VERSION 5.8 ;
BUSBITCHARS "[]" ;
DIVIDERCHAR "/" ;
UNITS
    DATABASE MICRONS 1000 ;
END UNITS

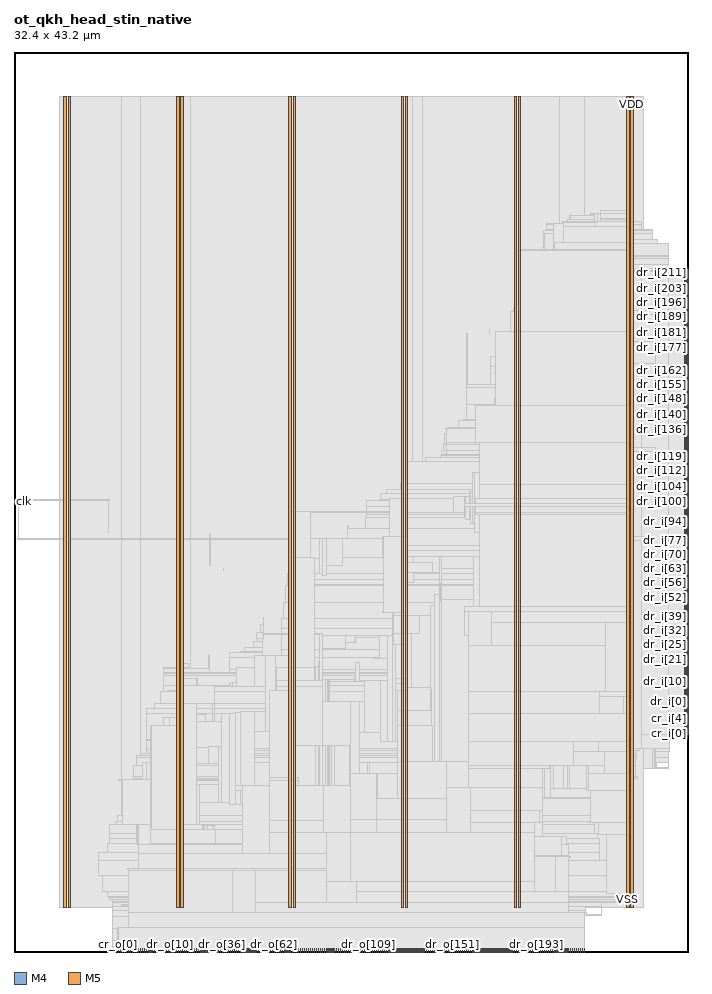
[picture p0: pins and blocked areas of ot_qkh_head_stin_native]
MACRO ot_qkh_head_stin_native
  FOREIGN ot_qkh_head_stin_native 0 0 ;
  CLASS BLOCK ;
  SIZE 32.4 BY 43.2 ;
  PIN clk
    DIRECTION INPUT ;
    USE SIGNAL ;
    PORT
      LAYER M4 ;
        RECT  0 21.6 0.192 21.624 ;
    END
  END clk
  PIN cr_i[0]
    DIRECTION INPUT ;
    USE SIGNAL ;
    PORT
      LAYER M4 ;
        RECT  32.208 10.464 32.4 10.488 ;
    END
  END cr_i[0]
  PIN cr_i[10]
    DIRECTION INPUT ;
    USE SIGNAL ;
    PORT
      LAYER M4 ;
        RECT  32.208 11.424 32.4 11.448 ;
    END
  END cr_i[10]
  PIN cr_i[11]
    DIRECTION INPUT ;
    USE SIGNAL ;
    PORT
      LAYER M4 ;
        RECT  32.208 11.52 32.4 11.544 ;
    END
  END cr_i[11]
  PIN cr_i[12]
    DIRECTION INPUT ;
    USE SIGNAL ;
    PORT
      LAYER M4 ;
        RECT  32.208 11.616 32.4 11.64 ;
    END
  END cr_i[12]
  PIN cr_i[13]
    DIRECTION INPUT ;
    USE SIGNAL ;
    PORT
      LAYER M4 ;
        RECT  32.208 11.712 32.4 11.736 ;
    END
  END cr_i[13]
  PIN cr_i[14]
    DIRECTION INPUT ;
    USE SIGNAL ;
    PORT
      LAYER M4 ;
        RECT  32.208 11.808 32.4 11.832 ;
    END
  END cr_i[14]
  PIN cr_i[15]
    DIRECTION INPUT ;
    USE SIGNAL ;
    PORT
      LAYER M4 ;
        RECT  32.208 11.904 32.4 11.928 ;
    END
  END cr_i[15]
  PIN cr_i[1]
    DIRECTION INPUT ;
    USE SIGNAL ;
    PORT
      LAYER M4 ;
        RECT  32.208 10.56 32.4 10.584 ;
    END
  END cr_i[1]
  PIN cr_i[2]
    DIRECTION INPUT ;
    USE SIGNAL ;
    PORT
      LAYER M4 ;
        RECT  32.208 10.656 32.4 10.68 ;
    END
  END cr_i[2]
  PIN cr_i[3]
    DIRECTION INPUT ;
    USE SIGNAL ;
    PORT
      LAYER M4 ;
        RECT  32.208 10.752 32.4 10.776 ;
    END
  END cr_i[3]
  PIN cr_i[4]
    DIRECTION INPUT ;
    USE SIGNAL ;
    PORT
      LAYER M4 ;
        RECT  32.208 10.848 32.4 10.872 ;
    END
  END cr_i[4]
  PIN cr_i[5]
    DIRECTION INPUT ;
    USE SIGNAL ;
    PORT
      LAYER M4 ;
        RECT  32.208 10.944 32.4 10.968 ;
    END
  END cr_i[5]
  PIN cr_i[6]
    DIRECTION INPUT ;
    USE SIGNAL ;
    PORT
      LAYER M4 ;
        RECT  32.208 11.04 32.4 11.064 ;
    END
  END cr_i[6]
  PIN cr_i[7]
    DIRECTION INPUT ;
    USE SIGNAL ;
    PORT
      LAYER M4 ;
        RECT  32.208 11.136 32.4 11.16 ;
    END
  END cr_i[7]
  PIN cr_i[8]
    DIRECTION INPUT ;
    USE SIGNAL ;
    PORT
      LAYER M4 ;
        RECT  32.208 11.232 32.4 11.256 ;
    END
  END cr_i[8]
  PIN cr_i[9]
    DIRECTION INPUT ;
    USE SIGNAL ;
    PORT
      LAYER M4 ;
        RECT  32.208 11.328 32.4 11.352 ;
    END
  END cr_i[9]
  PIN cr_o[0]
    DIRECTION OUTPUT ;
    USE SIGNAL ;
    PORT
      LAYER M5 ;
        RECT  4.992 0 5.016 0.192 ;
    END
  END cr_o[0]
  PIN cr_o[10]
    DIRECTION OUTPUT ;
    USE SIGNAL ;
    PORT
      LAYER M5 ;
        RECT  5.952 0 5.976 0.192 ;
    END
  END cr_o[10]
  PIN cr_o[11]
    DIRECTION OUTPUT ;
    USE SIGNAL ;
    PORT
      LAYER M5 ;
        RECT  6.048 0 6.072 0.192 ;
    END
  END cr_o[11]
  PIN cr_o[12]
    DIRECTION OUTPUT ;
    USE SIGNAL ;
    PORT
      LAYER M5 ;
        RECT  6.144 0 6.168 0.192 ;
    END
  END cr_o[12]
  PIN cr_o[13]
    DIRECTION OUTPUT ;
    USE SIGNAL ;
    PORT
      LAYER M5 ;
        RECT  6.24 0 6.264 0.192 ;
    END
  END cr_o[13]
  PIN cr_o[14]
    DIRECTION OUTPUT ;
    USE SIGNAL ;
    PORT
      LAYER M5 ;
        RECT  6.336 0 6.36 0.192 ;
    END
  END cr_o[14]
  PIN cr_o[15]
    DIRECTION OUTPUT ;
    USE SIGNAL ;
    PORT
      LAYER M5 ;
        RECT  6.432 0 6.456 0.192 ;
    END
  END cr_o[15]
  PIN cr_o[1]
    DIRECTION OUTPUT ;
    USE SIGNAL ;
    PORT
      LAYER M5 ;
        RECT  5.088 0 5.112 0.192 ;
    END
  END cr_o[1]
  PIN cr_o[2]
    DIRECTION OUTPUT ;
    USE SIGNAL ;
    PORT
      LAYER M5 ;
        RECT  5.184 0 5.208 0.192 ;
    END
  END cr_o[2]
  PIN cr_o[3]
    DIRECTION OUTPUT ;
    USE SIGNAL ;
    PORT
      LAYER M5 ;
        RECT  5.28 0 5.304 0.192 ;
    END
  END cr_o[3]
  PIN cr_o[4]
    DIRECTION OUTPUT ;
    USE SIGNAL ;
    PORT
      LAYER M5 ;
        RECT  5.376 0 5.4 0.192 ;
    END
  END cr_o[4]
  PIN cr_o[5]
    DIRECTION OUTPUT ;
    USE SIGNAL ;
    PORT
      LAYER M5 ;
        RECT  5.472 0 5.496 0.192 ;
    END
  END cr_o[5]
  PIN cr_o[6]
    DIRECTION OUTPUT ;
    USE SIGNAL ;
    PORT
      LAYER M5 ;
        RECT  5.568 0 5.592 0.192 ;
    END
  END cr_o[6]
  PIN cr_o[7]
    DIRECTION OUTPUT ;
    USE SIGNAL ;
    PORT
      LAYER M5 ;
        RECT  5.664 0 5.688 0.192 ;
    END
  END cr_o[7]
  PIN cr_o[8]
    DIRECTION OUTPUT ;
    USE SIGNAL ;
    PORT
      LAYER M5 ;
        RECT  5.76 0 5.784 0.192 ;
    END
  END cr_o[8]
  PIN cr_o[9]
    DIRECTION OUTPUT ;
    USE SIGNAL ;
    PORT
      LAYER M5 ;
        RECT  5.856 0 5.88 0.192 ;
    END
  END cr_o[9]
  PIN dr_i[0]
    DIRECTION INPUT ;
    USE SIGNAL ;
    PORT
      LAYER M4 ;
        RECT  32.208 12 32.4 12.024 ;
    END
  END dr_i[0]
  PIN dr_i[100]
    DIRECTION INPUT ;
    USE SIGNAL ;
    PORT
      LAYER M4 ;
        RECT  32.208 21.6 32.4 21.624 ;
    END
  END dr_i[100]
  PIN dr_i[101]
    DIRECTION INPUT ;
    USE SIGNAL ;
    PORT
      LAYER M4 ;
        RECT  32.208 21.696 32.4 21.72 ;
    END
  END dr_i[101]
  PIN dr_i[102]
    DIRECTION INPUT ;
    USE SIGNAL ;
    PORT
      LAYER M4 ;
        RECT  32.208 21.792 32.4 21.816 ;
    END
  END dr_i[102]
  PIN dr_i[103]
    DIRECTION INPUT ;
    USE SIGNAL ;
    PORT
      LAYER M4 ;
        RECT  32.208 21.888 32.4 21.912 ;
    END
  END dr_i[103]
  PIN dr_i[104]
    DIRECTION INPUT ;
    USE SIGNAL ;
    PORT
      LAYER M4 ;
        RECT  32.208 21.984 32.4 22.008 ;
    END
  END dr_i[104]
  PIN dr_i[105]
    DIRECTION INPUT ;
    USE SIGNAL ;
    PORT
      LAYER M4 ;
        RECT  32.208 22.08 32.4 22.104 ;
    END
  END dr_i[105]
  PIN dr_i[106]
    DIRECTION INPUT ;
    USE SIGNAL ;
    PORT
      LAYER M4 ;
        RECT  32.208 22.176 32.4 22.2 ;
    END
  END dr_i[106]
  PIN dr_i[107]
    DIRECTION INPUT ;
    USE SIGNAL ;
    PORT
      LAYER M4 ;
        RECT  32.208 22.272 32.4 22.296 ;
    END
  END dr_i[107]
  PIN dr_i[108]
    DIRECTION INPUT ;
    USE SIGNAL ;
    PORT
      LAYER M4 ;
        RECT  32.208 22.368 32.4 22.392 ;
    END
  END dr_i[108]
  PIN dr_i[109]
    DIRECTION INPUT ;
    USE SIGNAL ;
    PORT
      LAYER M4 ;
        RECT  32.208 22.464 32.4 22.488 ;
    END
  END dr_i[109]
  PIN dr_i[10]
    DIRECTION INPUT ;
    USE SIGNAL ;
    PORT
      LAYER M4 ;
        RECT  32.208 12.96 32.4 12.984 ;
    END
  END dr_i[10]
  PIN dr_i[110]
    DIRECTION INPUT ;
    USE SIGNAL ;
    PORT
      LAYER M4 ;
        RECT  32.208 22.56 32.4 22.584 ;
    END
  END dr_i[110]
  PIN dr_i[111]
    DIRECTION INPUT ;
    USE SIGNAL ;
    PORT
      LAYER M4 ;
        RECT  32.208 22.656 32.4 22.68 ;
    END
  END dr_i[111]
  PIN dr_i[112]
    DIRECTION INPUT ;
    USE SIGNAL ;
    PORT
      LAYER M4 ;
        RECT  32.208 22.752 32.4 22.776 ;
    END
  END dr_i[112]
  PIN dr_i[113]
    DIRECTION INPUT ;
    USE SIGNAL ;
    PORT
      LAYER M4 ;
        RECT  32.208 22.848 32.4 22.872 ;
    END
  END dr_i[113]
  PIN dr_i[114]
    DIRECTION INPUT ;
    USE SIGNAL ;
    PORT
      LAYER M4 ;
        RECT  32.208 22.944 32.4 22.968 ;
    END
  END dr_i[114]
  PIN dr_i[115]
    DIRECTION INPUT ;
    USE SIGNAL ;
    PORT
      LAYER M4 ;
        RECT  32.208 23.04 32.4 23.064 ;
    END
  END dr_i[115]
  PIN dr_i[116]
    DIRECTION INPUT ;
    USE SIGNAL ;
    PORT
      LAYER M4 ;
        RECT  32.208 23.136 32.4 23.16 ;
    END
  END dr_i[116]
  PIN dr_i[117]
    DIRECTION INPUT ;
    USE SIGNAL ;
    PORT
      LAYER M4 ;
        RECT  32.208 23.232 32.4 23.256 ;
    END
  END dr_i[117]
  PIN dr_i[118]
    DIRECTION INPUT ;
    USE SIGNAL ;
    PORT
      LAYER M4 ;
        RECT  32.208 23.328 32.4 23.352 ;
    END
  END dr_i[118]
  PIN dr_i[119]
    DIRECTION INPUT ;
    USE SIGNAL ;
    PORT
      LAYER M4 ;
        RECT  32.208 23.424 32.4 23.448 ;
    END
  END dr_i[119]
  PIN dr_i[11]
    DIRECTION INPUT ;
    USE SIGNAL ;
    PORT
      LAYER M4 ;
        RECT  32.208 13.056 32.4 13.08 ;
    END
  END dr_i[11]
  PIN dr_i[120]
    DIRECTION INPUT ;
    USE SIGNAL ;
    PORT
      LAYER M4 ;
        RECT  32.208 23.52 32.4 23.544 ;
    END
  END dr_i[120]
  PIN dr_i[121]
    DIRECTION INPUT ;
    USE SIGNAL ;
    PORT
      LAYER M4 ;
        RECT  32.208 23.616 32.4 23.64 ;
    END
  END dr_i[121]
  PIN dr_i[122]
    DIRECTION INPUT ;
    USE SIGNAL ;
    PORT
      LAYER M4 ;
        RECT  32.208 23.712 32.4 23.736 ;
    END
  END dr_i[122]
  PIN dr_i[123]
    DIRECTION INPUT ;
    USE SIGNAL ;
    PORT
      LAYER M4 ;
        RECT  32.208 23.808 32.4 23.832 ;
    END
  END dr_i[123]
  PIN dr_i[124]
    DIRECTION INPUT ;
    USE SIGNAL ;
    PORT
      LAYER M4 ;
        RECT  32.208 23.904 32.4 23.928 ;
    END
  END dr_i[124]
  PIN dr_i[125]
    DIRECTION INPUT ;
    USE SIGNAL ;
    PORT
      LAYER M4 ;
        RECT  32.208 24 32.4 24.024 ;
    END
  END dr_i[125]
  PIN dr_i[126]
    DIRECTION INPUT ;
    USE SIGNAL ;
    PORT
      LAYER M4 ;
        RECT  32.208 24.096 32.4 24.12 ;
    END
  END dr_i[126]
  PIN dr_i[127]
    DIRECTION INPUT ;
    USE SIGNAL ;
    PORT
      LAYER M4 ;
        RECT  32.208 24.192 32.4 24.216 ;
    END
  END dr_i[127]
  PIN dr_i[128]
    DIRECTION INPUT ;
    USE SIGNAL ;
    PORT
      LAYER M4 ;
        RECT  32.208 24.288 32.4 24.312 ;
    END
  END dr_i[128]
  PIN dr_i[129]
    DIRECTION INPUT ;
    USE SIGNAL ;
    PORT
      LAYER M4 ;
        RECT  32.208 24.384 32.4 24.408 ;
    END
  END dr_i[129]
  PIN dr_i[12]
    DIRECTION INPUT ;
    USE SIGNAL ;
    PORT
      LAYER M4 ;
        RECT  32.208 13.152 32.4 13.176 ;
    END
  END dr_i[12]
  PIN dr_i[130]
    DIRECTION INPUT ;
    USE SIGNAL ;
    PORT
      LAYER M4 ;
        RECT  32.208 24.48 32.4 24.504 ;
    END
  END dr_i[130]
  PIN dr_i[131]
    DIRECTION INPUT ;
    USE SIGNAL ;
    PORT
      LAYER M4 ;
        RECT  32.208 24.576 32.4 24.6 ;
    END
  END dr_i[131]
  PIN dr_i[132]
    DIRECTION INPUT ;
    USE SIGNAL ;
    PORT
      LAYER M4 ;
        RECT  32.208 24.672 32.4 24.696 ;
    END
  END dr_i[132]
  PIN dr_i[133]
    DIRECTION INPUT ;
    USE SIGNAL ;
    PORT
      LAYER M4 ;
        RECT  32.208 24.768 32.4 24.792 ;
    END
  END dr_i[133]
  PIN dr_i[134]
    DIRECTION INPUT ;
    USE SIGNAL ;
    PORT
      LAYER M4 ;
        RECT  32.208 24.864 32.4 24.888 ;
    END
  END dr_i[134]
  PIN dr_i[135]
    DIRECTION INPUT ;
    USE SIGNAL ;
    PORT
      LAYER M4 ;
        RECT  32.208 24.96 32.4 24.984 ;
    END
  END dr_i[135]
  PIN dr_i[136]
    DIRECTION INPUT ;
    USE SIGNAL ;
    PORT
      LAYER M4 ;
        RECT  32.208 25.056 32.4 25.08 ;
    END
  END dr_i[136]
  PIN dr_i[137]
    DIRECTION INPUT ;
    USE SIGNAL ;
    PORT
      LAYER M4 ;
        RECT  32.208 25.152 32.4 25.176 ;
    END
  END dr_i[137]
  PIN dr_i[138]
    DIRECTION INPUT ;
    USE SIGNAL ;
    PORT
      LAYER M4 ;
        RECT  32.208 25.248 32.4 25.272 ;
    END
  END dr_i[138]
  PIN dr_i[139]
    DIRECTION INPUT ;
    USE SIGNAL ;
    PORT
      LAYER M4 ;
        RECT  32.208 25.344 32.4 25.368 ;
    END
  END dr_i[139]
  PIN dr_i[13]
    DIRECTION INPUT ;
    USE SIGNAL ;
    PORT
      LAYER M4 ;
        RECT  32.208 13.248 32.4 13.272 ;
    END
  END dr_i[13]
  PIN dr_i[140]
    DIRECTION INPUT ;
    USE SIGNAL ;
    PORT
      LAYER M4 ;
        RECT  32.208 25.44 32.4 25.464 ;
    END
  END dr_i[140]
  PIN dr_i[141]
    DIRECTION INPUT ;
    USE SIGNAL ;
    PORT
      LAYER M4 ;
        RECT  32.208 25.536 32.4 25.56 ;
    END
  END dr_i[141]
  PIN dr_i[142]
    DIRECTION INPUT ;
    USE SIGNAL ;
    PORT
      LAYER M4 ;
        RECT  32.208 25.632 32.4 25.656 ;
    END
  END dr_i[142]
  PIN dr_i[143]
    DIRECTION INPUT ;
    USE SIGNAL ;
    PORT
      LAYER M4 ;
        RECT  32.208 25.728 32.4 25.752 ;
    END
  END dr_i[143]
  PIN dr_i[144]
    DIRECTION INPUT ;
    USE SIGNAL ;
    PORT
      LAYER M4 ;
        RECT  32.208 25.824 32.4 25.848 ;
    END
  END dr_i[144]
  PIN dr_i[145]
    DIRECTION INPUT ;
    USE SIGNAL ;
    PORT
      LAYER M4 ;
        RECT  32.208 25.92 32.4 25.944 ;
    END
  END dr_i[145]
  PIN dr_i[146]
    DIRECTION INPUT ;
    USE SIGNAL ;
    PORT
      LAYER M4 ;
        RECT  32.208 26.016 32.4 26.04 ;
    END
  END dr_i[146]
  PIN dr_i[147]
    DIRECTION INPUT ;
    USE SIGNAL ;
    PORT
      LAYER M4 ;
        RECT  32.208 26.112 32.4 26.136 ;
    END
  END dr_i[147]
  PIN dr_i[148]
    DIRECTION INPUT ;
    USE SIGNAL ;
    PORT
      LAYER M4 ;
        RECT  32.208 26.208 32.4 26.232 ;
    END
  END dr_i[148]
  PIN dr_i[149]
    DIRECTION INPUT ;
    USE SIGNAL ;
    PORT
      LAYER M4 ;
        RECT  32.208 26.304 32.4 26.328 ;
    END
  END dr_i[149]
  PIN dr_i[14]
    DIRECTION INPUT ;
    USE SIGNAL ;
    PORT
      LAYER M4 ;
        RECT  32.208 13.344 32.4 13.368 ;
    END
  END dr_i[14]
  PIN dr_i[150]
    DIRECTION INPUT ;
    USE SIGNAL ;
    PORT
      LAYER M4 ;
        RECT  32.208 26.4 32.4 26.424 ;
    END
  END dr_i[150]
  PIN dr_i[151]
    DIRECTION INPUT ;
    USE SIGNAL ;
    PORT
      LAYER M4 ;
        RECT  32.208 26.496 32.4 26.52 ;
    END
  END dr_i[151]
  PIN dr_i[152]
    DIRECTION INPUT ;
    USE SIGNAL ;
    PORT
      LAYER M4 ;
        RECT  32.208 26.592 32.4 26.616 ;
    END
  END dr_i[152]
  PIN dr_i[153]
    DIRECTION INPUT ;
    USE SIGNAL ;
    PORT
      LAYER M4 ;
        RECT  32.208 26.688 32.4 26.712 ;
    END
  END dr_i[153]
  PIN dr_i[154]
    DIRECTION INPUT ;
    USE SIGNAL ;
    PORT
      LAYER M4 ;
        RECT  32.208 26.784 32.4 26.808 ;
    END
  END dr_i[154]
  PIN dr_i[155]
    DIRECTION INPUT ;
    USE SIGNAL ;
    PORT
      LAYER M4 ;
        RECT  32.208 26.88 32.4 26.904 ;
    END
  END dr_i[155]
  PIN dr_i[156]
    DIRECTION INPUT ;
    USE SIGNAL ;
    PORT
      LAYER M4 ;
        RECT  32.208 26.976 32.4 27 ;
    END
  END dr_i[156]
  PIN dr_i[157]
    DIRECTION INPUT ;
    USE SIGNAL ;
    PORT
      LAYER M4 ;
        RECT  32.208 27.072 32.4 27.096 ;
    END
  END dr_i[157]
  PIN dr_i[158]
    DIRECTION INPUT ;
    USE SIGNAL ;
    PORT
      LAYER M4 ;
        RECT  32.208 27.168 32.4 27.192 ;
    END
  END dr_i[158]
  PIN dr_i[159]
    DIRECTION INPUT ;
    USE SIGNAL ;
    PORT
      LAYER M4 ;
        RECT  32.208 27.264 32.4 27.288 ;
    END
  END dr_i[159]
  PIN dr_i[15]
    DIRECTION INPUT ;
    USE SIGNAL ;
    PORT
      LAYER M4 ;
        RECT  32.208 13.44 32.4 13.464 ;
    END
  END dr_i[15]
  PIN dr_i[160]
    DIRECTION INPUT ;
    USE SIGNAL ;
    PORT
      LAYER M4 ;
        RECT  32.208 27.36 32.4 27.384 ;
    END
  END dr_i[160]
  PIN dr_i[161]
    DIRECTION INPUT ;
    USE SIGNAL ;
    PORT
      LAYER M4 ;
        RECT  32.208 27.456 32.4 27.48 ;
    END
  END dr_i[161]
  PIN dr_i[162]
    DIRECTION INPUT ;
    USE SIGNAL ;
    PORT
      LAYER M4 ;
        RECT  32.208 27.552 32.4 27.576 ;
    END
  END dr_i[162]
  PIN dr_i[163]
    DIRECTION INPUT ;
    USE SIGNAL ;
    PORT
      LAYER M4 ;
        RECT  32.208 27.648 32.4 27.672 ;
    END
  END dr_i[163]
  PIN dr_i[164]
    DIRECTION INPUT ;
    USE SIGNAL ;
    PORT
      LAYER M4 ;
        RECT  32.208 27.744 32.4 27.768 ;
    END
  END dr_i[164]
  PIN dr_i[165]
    DIRECTION INPUT ;
    USE SIGNAL ;
    PORT
      LAYER M4 ;
        RECT  32.208 27.84 32.4 27.864 ;
    END
  END dr_i[165]
  PIN dr_i[166]
    DIRECTION INPUT ;
    USE SIGNAL ;
    PORT
      LAYER M4 ;
        RECT  32.208 27.936 32.4 27.96 ;
    END
  END dr_i[166]
  PIN dr_i[167]
    DIRECTION INPUT ;
    USE SIGNAL ;
    PORT
      LAYER M4 ;
        RECT  32.208 28.032 32.4 28.056 ;
    END
  END dr_i[167]
  PIN dr_i[168]
    DIRECTION INPUT ;
    USE SIGNAL ;
    PORT
      LAYER M4 ;
        RECT  32.208 28.128 32.4 28.152 ;
    END
  END dr_i[168]
  PIN dr_i[169]
    DIRECTION INPUT ;
    USE SIGNAL ;
    PORT
      LAYER M4 ;
        RECT  32.208 28.224 32.4 28.248 ;
    END
  END dr_i[169]
  PIN dr_i[16]
    DIRECTION INPUT ;
    USE SIGNAL ;
    PORT
      LAYER M4 ;
        RECT  32.208 13.536 32.4 13.56 ;
    END
  END dr_i[16]
  PIN dr_i[170]
    DIRECTION INPUT ;
    USE SIGNAL ;
    PORT
      LAYER M4 ;
        RECT  32.208 28.32 32.4 28.344 ;
    END
  END dr_i[170]
  PIN dr_i[171]
    DIRECTION INPUT ;
    USE SIGNAL ;
    PORT
      LAYER M4 ;
        RECT  32.208 28.416 32.4 28.44 ;
    END
  END dr_i[171]
  PIN dr_i[172]
    DIRECTION INPUT ;
    USE SIGNAL ;
    PORT
      LAYER M4 ;
        RECT  32.208 28.512 32.4 28.536 ;
    END
  END dr_i[172]
  PIN dr_i[173]
    DIRECTION INPUT ;
    USE SIGNAL ;
    PORT
      LAYER M4 ;
        RECT  32.208 28.608 32.4 28.632 ;
    END
  END dr_i[173]
  PIN dr_i[174]
    DIRECTION INPUT ;
    USE SIGNAL ;
    PORT
      LAYER M4 ;
        RECT  32.208 28.704 32.4 28.728 ;
    END
  END dr_i[174]
  PIN dr_i[175]
    DIRECTION INPUT ;
    USE SIGNAL ;
    PORT
      LAYER M4 ;
        RECT  32.208 28.8 32.4 28.824 ;
    END
  END dr_i[175]
  PIN dr_i[176]
    DIRECTION INPUT ;
    USE SIGNAL ;
    PORT
      LAYER M4 ;
        RECT  32.208 28.896 32.4 28.92 ;
    END
  END dr_i[176]
  PIN dr_i[177]
    DIRECTION INPUT ;
    USE SIGNAL ;
    PORT
      LAYER M4 ;
        RECT  32.208 28.992 32.4 29.016 ;
    END
  END dr_i[177]
  PIN dr_i[178]
    DIRECTION INPUT ;
    USE SIGNAL ;
    PORT
      LAYER M4 ;
        RECT  32.208 29.088 32.4 29.112 ;
    END
  END dr_i[178]
  PIN dr_i[179]
    DIRECTION INPUT ;
    USE SIGNAL ;
    PORT
      LAYER M4 ;
        RECT  32.208 29.184 32.4 29.208 ;
    END
  END dr_i[179]
  PIN dr_i[17]
    DIRECTION INPUT ;
    USE SIGNAL ;
    PORT
      LAYER M4 ;
        RECT  32.208 13.632 32.4 13.656 ;
    END
  END dr_i[17]
  PIN dr_i[180]
    DIRECTION INPUT ;
    USE SIGNAL ;
    PORT
      LAYER M4 ;
        RECT  32.208 29.28 32.4 29.304 ;
    END
  END dr_i[180]
  PIN dr_i[181]
    DIRECTION INPUT ;
    USE SIGNAL ;
    PORT
      LAYER M4 ;
        RECT  32.208 29.376 32.4 29.4 ;
    END
  END dr_i[181]
  PIN dr_i[182]
    DIRECTION INPUT ;
    USE SIGNAL ;
    PORT
      LAYER M4 ;
        RECT  32.208 29.472 32.4 29.496 ;
    END
  END dr_i[182]
  PIN dr_i[183]
    DIRECTION INPUT ;
    USE SIGNAL ;
    PORT
      LAYER M4 ;
        RECT  32.208 29.568 32.4 29.592 ;
    END
  END dr_i[183]
  PIN dr_i[184]
    DIRECTION INPUT ;
    USE SIGNAL ;
    PORT
      LAYER M4 ;
        RECT  32.208 29.664 32.4 29.688 ;
    END
  END dr_i[184]
  PIN dr_i[185]
    DIRECTION INPUT ;
    USE SIGNAL ;
    PORT
      LAYER M4 ;
        RECT  32.208 29.76 32.4 29.784 ;
    END
  END dr_i[185]
  PIN dr_i[186]
    DIRECTION INPUT ;
    USE SIGNAL ;
    PORT
      LAYER M4 ;
        RECT  32.208 29.856 32.4 29.88 ;
    END
  END dr_i[186]
  PIN dr_i[187]
    DIRECTION INPUT ;
    USE SIGNAL ;
    PORT
      LAYER M4 ;
        RECT  32.208 29.952 32.4 29.976 ;
    END
  END dr_i[187]
  PIN dr_i[188]
    DIRECTION INPUT ;
    USE SIGNAL ;
    PORT
      LAYER M4 ;
        RECT  32.208 30.048 32.4 30.072 ;
    END
  END dr_i[188]
  PIN dr_i[189]
    DIRECTION INPUT ;
    USE SIGNAL ;
    PORT
      LAYER M4 ;
        RECT  32.208 30.144 32.4 30.168 ;
    END
  END dr_i[189]
  PIN dr_i[18]
    DIRECTION INPUT ;
    USE SIGNAL ;
    PORT
      LAYER M4 ;
        RECT  32.208 13.728 32.4 13.752 ;
    END
  END dr_i[18]
  PIN dr_i[190]
    DIRECTION INPUT ;
    USE SIGNAL ;
    PORT
      LAYER M4 ;
        RECT  32.208 30.24 32.4 30.264 ;
    END
  END dr_i[190]
  PIN dr_i[191]
    DIRECTION INPUT ;
    USE SIGNAL ;
    PORT
      LAYER M4 ;
        RECT  32.208 30.336 32.4 30.36 ;
    END
  END dr_i[191]
  PIN dr_i[192]
    DIRECTION INPUT ;
    USE SIGNAL ;
    PORT
      LAYER M4 ;
        RECT  32.208 30.432 32.4 30.456 ;
    END
  END dr_i[192]
  PIN dr_i[193]
    DIRECTION INPUT ;
    USE SIGNAL ;
    PORT
      LAYER M4 ;
        RECT  32.208 30.528 32.4 30.552 ;
    END
  END dr_i[193]
  PIN dr_i[194]
    DIRECTION INPUT ;
    USE SIGNAL ;
    PORT
      LAYER M4 ;
        RECT  32.208 30.624 32.4 30.648 ;
    END
  END dr_i[194]
  PIN dr_i[195]
    DIRECTION INPUT ;
    USE SIGNAL ;
    PORT
      LAYER M4 ;
        RECT  32.208 30.72 32.4 30.744 ;
    END
  END dr_i[195]
  PIN dr_i[196]
    DIRECTION INPUT ;
    USE SIGNAL ;
    PORT
      LAYER M4 ;
        RECT  32.208 30.816 32.4 30.84 ;
    END
  END dr_i[196]
  PIN dr_i[197]
    DIRECTION INPUT ;
    USE SIGNAL ;
    PORT
      LAYER M4 ;
        RECT  32.208 30.912 32.4 30.936 ;
    END
  END dr_i[197]
  PIN dr_i[198]
    DIRECTION INPUT ;
    USE SIGNAL ;
    PORT
      LAYER M4 ;
        RECT  32.208 31.008 32.4 31.032 ;
    END
  END dr_i[198]
  PIN dr_i[199]
    DIRECTION INPUT ;
    USE SIGNAL ;
    PORT
      LAYER M4 ;
        RECT  32.208 31.104 32.4 31.128 ;
    END
  END dr_i[199]
  PIN dr_i[19]
    DIRECTION INPUT ;
    USE SIGNAL ;
    PORT
      LAYER M4 ;
        RECT  32.208 13.824 32.4 13.848 ;
    END
  END dr_i[19]
  PIN dr_i[1]
    DIRECTION INPUT ;
    USE SIGNAL ;
    PORT
      LAYER M4 ;
        RECT  32.208 12.096 32.4 12.12 ;
    END
  END dr_i[1]
  PIN dr_i[200]
    DIRECTION INPUT ;
    USE SIGNAL ;
    PORT
      LAYER M4 ;
        RECT  32.208 31.2 32.4 31.224 ;
    END
  END dr_i[200]
  PIN dr_i[201]
    DIRECTION INPUT ;
    USE SIGNAL ;
    PORT
      LAYER M4 ;
        RECT  32.208 31.296 32.4 31.32 ;
    END
  END dr_i[201]
  PIN dr_i[202]
    DIRECTION INPUT ;
    USE SIGNAL ;
    PORT
      LAYER M4 ;
        RECT  32.208 31.392 32.4 31.416 ;
    END
  END dr_i[202]
  PIN dr_i[203]
    DIRECTION INPUT ;
    USE SIGNAL ;
    PORT
      LAYER M4 ;
        RECT  32.208 31.488 32.4 31.512 ;
    END
  END dr_i[203]
  PIN dr_i[204]
    DIRECTION INPUT ;
    USE SIGNAL ;
    PORT
      LAYER M4 ;
        RECT  32.208 31.584 32.4 31.608 ;
    END
  END dr_i[204]
  PIN dr_i[205]
    DIRECTION INPUT ;
    USE SIGNAL ;
    PORT
      LAYER M4 ;
        RECT  32.208 31.68 32.4 31.704 ;
    END
  END dr_i[205]
  PIN dr_i[206]
    DIRECTION INPUT ;
    USE SIGNAL ;
    PORT
      LAYER M4 ;
        RECT  32.208 31.776 32.4 31.8 ;
    END
  END dr_i[206]
  PIN dr_i[207]
    DIRECTION INPUT ;
    USE SIGNAL ;
    PORT
      LAYER M4 ;
        RECT  32.208 31.872 32.4 31.896 ;
    END
  END dr_i[207]
  PIN dr_i[208]
    DIRECTION INPUT ;
    USE SIGNAL ;
    PORT
      LAYER M4 ;
        RECT  32.208 31.968 32.4 31.992 ;
    END
  END dr_i[208]
  PIN dr_i[209]
    DIRECTION INPUT ;
    USE SIGNAL ;
    PORT
      LAYER M4 ;
        RECT  32.208 32.064 32.4 32.088 ;
    END
  END dr_i[209]
  PIN dr_i[20]
    DIRECTION INPUT ;
    USE SIGNAL ;
    PORT
      LAYER M4 ;
        RECT  32.208 13.92 32.4 13.944 ;
    END
  END dr_i[20]
  PIN dr_i[210]
    DIRECTION INPUT ;
    USE SIGNAL ;
    PORT
      LAYER M4 ;
        RECT  32.208 32.16 32.4 32.184 ;
    END
  END dr_i[210]
  PIN dr_i[211]
    DIRECTION INPUT ;
    USE SIGNAL ;
    PORT
      LAYER M4 ;
        RECT  32.208 32.256 32.4 32.28 ;
    END
  END dr_i[211]
  PIN dr_i[212]
    DIRECTION INPUT ;
    USE SIGNAL ;
    PORT
      LAYER M4 ;
        RECT  32.208 32.352 32.4 32.376 ;
    END
  END dr_i[212]
  PIN dr_i[213]
    DIRECTION INPUT ;
    USE SIGNAL ;
    PORT
      LAYER M4 ;
        RECT  32.208 32.448 32.4 32.472 ;
    END
  END dr_i[213]
  PIN dr_i[214]
    DIRECTION INPUT ;
    USE SIGNAL ;
    PORT
      LAYER M4 ;
        RECT  32.208 32.544 32.4 32.568 ;
    END
  END dr_i[214]
  PIN dr_i[215]
    DIRECTION INPUT ;
    USE SIGNAL ;
    PORT
      LAYER M4 ;
        RECT  32.208 32.64 32.4 32.664 ;
    END
  END dr_i[215]
  PIN dr_i[216]
    DIRECTION INPUT ;
    USE SIGNAL ;
    PORT
      LAYER M4 ;
        RECT  32.208 32.736 32.4 32.76 ;
    END
  END dr_i[216]
  PIN dr_i[21]
    DIRECTION INPUT ;
    USE SIGNAL ;
    PORT
      LAYER M4 ;
        RECT  32.208 14.016 32.4 14.04 ;
    END
  END dr_i[21]
  PIN dr_i[22]
    DIRECTION INPUT ;
    USE SIGNAL ;
    PORT
      LAYER M4 ;
        RECT  32.208 14.112 32.4 14.136 ;
    END
  END dr_i[22]
  PIN dr_i[23]
    DIRECTION INPUT ;
    USE SIGNAL ;
    PORT
      LAYER M4 ;
        RECT  32.208 14.208 32.4 14.232 ;
    END
  END dr_i[23]
  PIN dr_i[24]
    DIRECTION INPUT ;
    USE SIGNAL ;
    PORT
      LAYER M4 ;
        RECT  32.208 14.304 32.4 14.328 ;
    END
  END dr_i[24]
  PIN dr_i[25]
    DIRECTION INPUT ;
    USE SIGNAL ;
    PORT
      LAYER M4 ;
        RECT  32.208 14.4 32.4 14.424 ;
    END
  END dr_i[25]
  PIN dr_i[26]
    DIRECTION INPUT ;
    USE SIGNAL ;
    PORT
      LAYER M4 ;
        RECT  32.208 14.496 32.4 14.52 ;
    END
  END dr_i[26]
  PIN dr_i[27]
    DIRECTION INPUT ;
    USE SIGNAL ;
    PORT
      LAYER M4 ;
        RECT  32.208 14.592 32.4 14.616 ;
    END
  END dr_i[27]
  PIN dr_i[28]
    DIRECTION INPUT ;
    USE SIGNAL ;
    PORT
      LAYER M4 ;
        RECT  32.208 14.688 32.4 14.712 ;
    END
  END dr_i[28]
  PIN dr_i[29]
    DIRECTION INPUT ;
    USE SIGNAL ;
    PORT
      LAYER M4 ;
        RECT  32.208 14.784 32.4 14.808 ;
    END
  END dr_i[29]
  PIN dr_i[2]
    DIRECTION INPUT ;
    USE SIGNAL ;
    PORT
      LAYER M4 ;
        RECT  32.208 12.192 32.4 12.216 ;
    END
  END dr_i[2]
  PIN dr_i[30]
    DIRECTION INPUT ;
    USE SIGNAL ;
    PORT
      LAYER M4 ;
        RECT  32.208 14.88 32.4 14.904 ;
    END
  END dr_i[30]
  PIN dr_i[31]
    DIRECTION INPUT ;
    USE SIGNAL ;
    PORT
      LAYER M4 ;
        RECT  32.208 14.976 32.4 15 ;
    END
  END dr_i[31]
  PIN dr_i[32]
    DIRECTION INPUT ;
    USE SIGNAL ;
    PORT
      LAYER M4 ;
        RECT  32.208 15.072 32.4 15.096 ;
    END
  END dr_i[32]
  PIN dr_i[33]
    DIRECTION INPUT ;
    USE SIGNAL ;
    PORT
      LAYER M4 ;
        RECT  32.208 15.168 32.4 15.192 ;
    END
  END dr_i[33]
  PIN dr_i[34]
    DIRECTION INPUT ;
    USE SIGNAL ;
    PORT
      LAYER M4 ;
        RECT  32.208 15.264 32.4 15.288 ;
    END
  END dr_i[34]
  PIN dr_i[35]
    DIRECTION INPUT ;
    USE SIGNAL ;
    PORT
      LAYER M4 ;
        RECT  32.208 15.36 32.4 15.384 ;
    END
  END dr_i[35]
  PIN dr_i[36]
    DIRECTION INPUT ;
    USE SIGNAL ;
    PORT
      LAYER M4 ;
        RECT  32.208 15.456 32.4 15.48 ;
    END
  END dr_i[36]
  PIN dr_i[37]
    DIRECTION INPUT ;
    USE SIGNAL ;
    PORT
      LAYER M4 ;
        RECT  32.208 15.552 32.4 15.576 ;
    END
  END dr_i[37]
  PIN dr_i[38]
    DIRECTION INPUT ;
    USE SIGNAL ;
    PORT
      LAYER M4 ;
        RECT  32.208 15.648 32.4 15.672 ;
    END
  END dr_i[38]
  PIN dr_i[39]
    DIRECTION INPUT ;
    USE SIGNAL ;
    PORT
      LAYER M4 ;
        RECT  32.208 15.744 32.4 15.768 ;
    END
  END dr_i[39]
  PIN dr_i[3]
    DIRECTION INPUT ;
    USE SIGNAL ;
    PORT
      LAYER M4 ;
        RECT  32.208 12.288 32.4 12.312 ;
    END
  END dr_i[3]
  PIN dr_i[40]
    DIRECTION INPUT ;
    USE SIGNAL ;
    PORT
      LAYER M4 ;
        RECT  32.208 15.84 32.4 15.864 ;
    END
  END dr_i[40]
  PIN dr_i[41]
    DIRECTION INPUT ;
    USE SIGNAL ;
    PORT
      LAYER M4 ;
        RECT  32.208 15.936 32.4 15.96 ;
    END
  END dr_i[41]
  PIN dr_i[42]
    DIRECTION INPUT ;
    USE SIGNAL ;
    PORT
      LAYER M4 ;
        RECT  32.208 16.032 32.4 16.056 ;
    END
  END dr_i[42]
  PIN dr_i[43]
    DIRECTION INPUT ;
    USE SIGNAL ;
    PORT
      LAYER M4 ;
        RECT  32.208 16.128 32.4 16.152 ;
    END
  END dr_i[43]
  PIN dr_i[44]
    DIRECTION INPUT ;
    USE SIGNAL ;
    PORT
      LAYER M4 ;
        RECT  32.208 16.224 32.4 16.248 ;
    END
  END dr_i[44]
  PIN dr_i[45]
    DIRECTION INPUT ;
    USE SIGNAL ;
    PORT
      LAYER M4 ;
        RECT  32.208 16.32 32.4 16.344 ;
    END
  END dr_i[45]
  PIN dr_i[46]
    DIRECTION INPUT ;
    USE SIGNAL ;
    PORT
      LAYER M4 ;
        RECT  32.208 16.416 32.4 16.44 ;
    END
  END dr_i[46]
  PIN dr_i[47]
    DIRECTION INPUT ;
    USE SIGNAL ;
    PORT
      LAYER M4 ;
        RECT  32.208 16.512 32.4 16.536 ;
    END
  END dr_i[47]
  PIN dr_i[48]
    DIRECTION INPUT ;
    USE SIGNAL ;
    PORT
      LAYER M4 ;
        RECT  32.208 16.608 32.4 16.632 ;
    END
  END dr_i[48]
  PIN dr_i[49]
    DIRECTION INPUT ;
    USE SIGNAL ;
    PORT
      LAYER M4 ;
        RECT  32.208 16.704 32.4 16.728 ;
    END
  END dr_i[49]
  PIN dr_i[4]
    DIRECTION INPUT ;
    USE SIGNAL ;
    PORT
      LAYER M4 ;
        RECT  32.208 12.384 32.4 12.408 ;
    END
  END dr_i[4]
  PIN dr_i[50]
    DIRECTION INPUT ;
    USE SIGNAL ;
    PORT
      LAYER M4 ;
        RECT  32.208 16.8 32.4 16.824 ;
    END
  END dr_i[50]
  PIN dr_i[51]
    DIRECTION INPUT ;
    USE SIGNAL ;
    PORT
      LAYER M4 ;
        RECT  32.208 16.896 32.4 16.92 ;
    END
  END dr_i[51]
  PIN dr_i[52]
    DIRECTION INPUT ;
    USE SIGNAL ;
    PORT
      LAYER M4 ;
        RECT  32.208 16.992 32.4 17.016 ;
    END
  END dr_i[52]
  PIN dr_i[53]
    DIRECTION INPUT ;
    USE SIGNAL ;
    PORT
      LAYER M4 ;
        RECT  32.208 17.088 32.4 17.112 ;
    END
  END dr_i[53]
  PIN dr_i[54]
    DIRECTION INPUT ;
    USE SIGNAL ;
    PORT
      LAYER M4 ;
        RECT  32.208 17.184 32.4 17.208 ;
    END
  END dr_i[54]
  PIN dr_i[55]
    DIRECTION INPUT ;
    USE SIGNAL ;
    PORT
      LAYER M4 ;
        RECT  32.208 17.28 32.4 17.304 ;
    END
  END dr_i[55]
  PIN dr_i[56]
    DIRECTION INPUT ;
    USE SIGNAL ;
    PORT
      LAYER M4 ;
        RECT  32.208 17.376 32.4 17.4 ;
    END
  END dr_i[56]
  PIN dr_i[57]
    DIRECTION INPUT ;
    USE SIGNAL ;
    PORT
      LAYER M4 ;
        RECT  32.208 17.472 32.4 17.496 ;
    END
  END dr_i[57]
  PIN dr_i[58]
    DIRECTION INPUT ;
    USE SIGNAL ;
    PORT
      LAYER M4 ;
        RECT  32.208 17.568 32.4 17.592 ;
    END
  END dr_i[58]
  PIN dr_i[59]
    DIRECTION INPUT ;
    USE SIGNAL ;
    PORT
      LAYER M4 ;
        RECT  32.208 17.664 32.4 17.688 ;
    END
  END dr_i[59]
  PIN dr_i[5]
    DIRECTION INPUT ;
    USE SIGNAL ;
    PORT
      LAYER M4 ;
        RECT  32.208 12.48 32.4 12.504 ;
    END
  END dr_i[5]
  PIN dr_i[60]
    DIRECTION INPUT ;
    USE SIGNAL ;
    PORT
      LAYER M4 ;
        RECT  32.208 17.76 32.4 17.784 ;
    END
  END dr_i[60]
  PIN dr_i[61]
    DIRECTION INPUT ;
    USE SIGNAL ;
    PORT
      LAYER M4 ;
        RECT  32.208 17.856 32.4 17.88 ;
    END
  END dr_i[61]
  PIN dr_i[62]
    DIRECTION INPUT ;
    USE SIGNAL ;
    PORT
      LAYER M4 ;
        RECT  32.208 17.952 32.4 17.976 ;
    END
  END dr_i[62]
  PIN dr_i[63]
    DIRECTION INPUT ;
    USE SIGNAL ;
    PORT
      LAYER M4 ;
        RECT  32.208 18.048 32.4 18.072 ;
    END
  END dr_i[63]
  PIN dr_i[64]
    DIRECTION INPUT ;
    USE SIGNAL ;
    PORT
      LAYER M4 ;
        RECT  32.208 18.144 32.4 18.168 ;
    END
  END dr_i[64]
  PIN dr_i[65]
    DIRECTION INPUT ;
    USE SIGNAL ;
    PORT
      LAYER M4 ;
        RECT  32.208 18.24 32.4 18.264 ;
    END
  END dr_i[65]
  PIN dr_i[66]
    DIRECTION INPUT ;
    USE SIGNAL ;
    PORT
      LAYER M4 ;
        RECT  32.208 18.336 32.4 18.36 ;
    END
  END dr_i[66]
  PIN dr_i[67]
    DIRECTION INPUT ;
    USE SIGNAL ;
    PORT
      LAYER M4 ;
        RECT  32.208 18.432 32.4 18.456 ;
    END
  END dr_i[67]
  PIN dr_i[68]
    DIRECTION INPUT ;
    USE SIGNAL ;
    PORT
      LAYER M4 ;
        RECT  32.208 18.528 32.4 18.552 ;
    END
  END dr_i[68]
  PIN dr_i[69]
    DIRECTION INPUT ;
    USE SIGNAL ;
    PORT
      LAYER M4 ;
        RECT  32.208 18.624 32.4 18.648 ;
    END
  END dr_i[69]
  PIN dr_i[6]
    DIRECTION INPUT ;
    USE SIGNAL ;
    PORT
      LAYER M4 ;
        RECT  32.208 12.576 32.4 12.6 ;
    END
  END dr_i[6]
  PIN dr_i[70]
    DIRECTION INPUT ;
    USE SIGNAL ;
    PORT
      LAYER M4 ;
        RECT  32.208 18.72 32.4 18.744 ;
    END
  END dr_i[70]
  PIN dr_i[71]
    DIRECTION INPUT ;
    USE SIGNAL ;
    PORT
      LAYER M4 ;
        RECT  32.208 18.816 32.4 18.84 ;
    END
  END dr_i[71]
  PIN dr_i[72]
    DIRECTION INPUT ;
    USE SIGNAL ;
    PORT
      LAYER M4 ;
        RECT  32.208 18.912 32.4 18.936 ;
    END
  END dr_i[72]
  PIN dr_i[73]
    DIRECTION INPUT ;
    USE SIGNAL ;
    PORT
      LAYER M4 ;
        RECT  32.208 19.008 32.4 19.032 ;
    END
  END dr_i[73]
  PIN dr_i[74]
    DIRECTION INPUT ;
    USE SIGNAL ;
    PORT
      LAYER M4 ;
        RECT  32.208 19.104 32.4 19.128 ;
    END
  END dr_i[74]
  PIN dr_i[75]
    DIRECTION INPUT ;
    USE SIGNAL ;
    PORT
      LAYER M4 ;
        RECT  32.208 19.2 32.4 19.224 ;
    END
  END dr_i[75]
  PIN dr_i[76]
    DIRECTION INPUT ;
    USE SIGNAL ;
    PORT
      LAYER M4 ;
        RECT  32.208 19.296 32.4 19.32 ;
    END
  END dr_i[76]
  PIN dr_i[77]
    DIRECTION INPUT ;
    USE SIGNAL ;
    PORT
      LAYER M4 ;
        RECT  32.208 19.392 32.4 19.416 ;
    END
  END dr_i[77]
  PIN dr_i[78]
    DIRECTION INPUT ;
    USE SIGNAL ;
    PORT
      LAYER M4 ;
        RECT  32.208 19.488 32.4 19.512 ;
    END
  END dr_i[78]
  PIN dr_i[79]
    DIRECTION INPUT ;
    USE SIGNAL ;
    PORT
      LAYER M4 ;
        RECT  32.208 19.584 32.4 19.608 ;
    END
  END dr_i[79]
  PIN dr_i[7]
    DIRECTION INPUT ;
    USE SIGNAL ;
    PORT
      LAYER M4 ;
        RECT  32.208 12.672 32.4 12.696 ;
    END
  END dr_i[7]
  PIN dr_i[80]
    DIRECTION INPUT ;
    USE SIGNAL ;
    PORT
      LAYER M4 ;
        RECT  32.208 19.68 32.4 19.704 ;
    END
  END dr_i[80]
  PIN dr_i[81]
    DIRECTION INPUT ;
    USE SIGNAL ;
    PORT
      LAYER M4 ;
        RECT  32.208 19.776 32.4 19.8 ;
    END
  END dr_i[81]
  PIN dr_i[82]
    DIRECTION INPUT ;
    USE SIGNAL ;
    PORT
      LAYER M4 ;
        RECT  32.208 19.872 32.4 19.896 ;
    END
  END dr_i[82]
  PIN dr_i[83]
    DIRECTION INPUT ;
    USE SIGNAL ;
    PORT
      LAYER M4 ;
        RECT  32.208 19.968 32.4 19.992 ;
    END
  END dr_i[83]
  PIN dr_i[84]
    DIRECTION INPUT ;
    USE SIGNAL ;
    PORT
      LAYER M4 ;
        RECT  32.208 20.064 32.4 20.088 ;
    END
  END dr_i[84]
  PIN dr_i[85]
    DIRECTION INPUT ;
    USE SIGNAL ;
    PORT
      LAYER M4 ;
        RECT  32.208 20.16 32.4 20.184 ;
    END
  END dr_i[85]
  PIN dr_i[86]
    DIRECTION INPUT ;
    USE SIGNAL ;
    PORT
      LAYER M4 ;
        RECT  32.208 20.256 32.4 20.28 ;
    END
  END dr_i[86]
  PIN dr_i[87]
    DIRECTION INPUT ;
    USE SIGNAL ;
    PORT
      LAYER M4 ;
        RECT  32.208 20.352 32.4 20.376 ;
    END
  END dr_i[87]
  PIN dr_i[88]
    DIRECTION INPUT ;
    USE SIGNAL ;
    PORT
      LAYER M4 ;
        RECT  32.208 20.448 32.4 20.472 ;
    END
  END dr_i[88]
  PIN dr_i[89]
    DIRECTION INPUT ;
    USE SIGNAL ;
    PORT
      LAYER M4 ;
        RECT  32.208 20.544 32.4 20.568 ;
    END
  END dr_i[89]
  PIN dr_i[8]
    DIRECTION INPUT ;
    USE SIGNAL ;
    PORT
      LAYER M4 ;
        RECT  32.208 12.768 32.4 12.792 ;
    END
  END dr_i[8]
  PIN dr_i[90]
    DIRECTION INPUT ;
    USE SIGNAL ;
    PORT
      LAYER M4 ;
        RECT  32.208 20.64 32.4 20.664 ;
    END
  END dr_i[90]
  PIN dr_i[91]
    DIRECTION INPUT ;
    USE SIGNAL ;
    PORT
      LAYER M4 ;
        RECT  32.208 20.736 32.4 20.76 ;
    END
  END dr_i[91]
  PIN dr_i[92]
    DIRECTION INPUT ;
    USE SIGNAL ;
    PORT
      LAYER M4 ;
        RECT  32.208 20.832 32.4 20.856 ;
    END
  END dr_i[92]
  PIN dr_i[93]
    DIRECTION INPUT ;
    USE SIGNAL ;
    PORT
      LAYER M4 ;
        RECT  32.208 20.928 32.4 20.952 ;
    END
  END dr_i[93]
  PIN dr_i[94]
    DIRECTION INPUT ;
    USE SIGNAL ;
    PORT
      LAYER M4 ;
        RECT  32.208 21.024 32.4 21.048 ;
    END
  END dr_i[94]
  PIN dr_i[95]
    DIRECTION INPUT ;
    USE SIGNAL ;
    PORT
      LAYER M4 ;
        RECT  32.208 21.12 32.4 21.144 ;
    END
  END dr_i[95]
  PIN dr_i[96]
    DIRECTION INPUT ;
    USE SIGNAL ;
    PORT
      LAYER M4 ;
        RECT  32.208 21.216 32.4 21.24 ;
    END
  END dr_i[96]
  PIN dr_i[97]
    DIRECTION INPUT ;
    USE SIGNAL ;
    PORT
      LAYER M4 ;
        RECT  32.208 21.312 32.4 21.336 ;
    END
  END dr_i[97]
  PIN dr_i[98]
    DIRECTION INPUT ;
    USE SIGNAL ;
    PORT
      LAYER M4 ;
        RECT  32.208 21.408 32.4 21.432 ;
    END
  END dr_i[98]
  PIN dr_i[99]
    DIRECTION INPUT ;
    USE SIGNAL ;
    PORT
      LAYER M4 ;
        RECT  32.208 21.504 32.4 21.528 ;
    END
  END dr_i[99]
  PIN dr_i[9]
    DIRECTION INPUT ;
    USE SIGNAL ;
    PORT
      LAYER M4 ;
        RECT  32.208 12.864 32.4 12.888 ;
    END
  END dr_i[9]
  PIN dr_o[0]
    DIRECTION OUTPUT ;
    USE SIGNAL ;
    PORT
      LAYER M5 ;
        RECT  6.528 0 6.552 0.192 ;
    END
  END dr_o[0]
  PIN dr_o[100]
    DIRECTION OUTPUT ;
    USE SIGNAL ;
    PORT
      LAYER M5 ;
        RECT  16.128 0 16.152 0.192 ;
    END
  END dr_o[100]
  PIN dr_o[101]
    DIRECTION OUTPUT ;
    USE SIGNAL ;
    PORT
      LAYER M5 ;
        RECT  16.224 0 16.248 0.192 ;
    END
  END dr_o[101]
  PIN dr_o[102]
    DIRECTION OUTPUT ;
    USE SIGNAL ;
    PORT
      LAYER M5 ;
        RECT  16.32 0 16.344 0.192 ;
    END
  END dr_o[102]
  PIN dr_o[103]
    DIRECTION OUTPUT ;
    USE SIGNAL ;
    PORT
      LAYER M5 ;
        RECT  16.416 0 16.44 0.192 ;
    END
  END dr_o[103]
  PIN dr_o[104]
    DIRECTION OUTPUT ;
    USE SIGNAL ;
    PORT
      LAYER M5 ;
        RECT  16.512 0 16.536 0.192 ;
    END
  END dr_o[104]
  PIN dr_o[105]
    DIRECTION OUTPUT ;
    USE SIGNAL ;
    PORT
      LAYER M5 ;
        RECT  16.608 0 16.632 0.192 ;
    END
  END dr_o[105]
  PIN dr_o[106]
    DIRECTION OUTPUT ;
    USE SIGNAL ;
    PORT
      LAYER M5 ;
        RECT  16.704 0 16.728 0.192 ;
    END
  END dr_o[106]
  PIN dr_o[107]
    DIRECTION OUTPUT ;
    USE SIGNAL ;
    PORT
      LAYER M5 ;
        RECT  16.8 0 16.824 0.192 ;
    END
  END dr_o[107]
  PIN dr_o[108]
    DIRECTION OUTPUT ;
    USE SIGNAL ;
    PORT
      LAYER M5 ;
        RECT  16.896 0 16.92 0.192 ;
    END
  END dr_o[108]
  PIN dr_o[109]
    DIRECTION OUTPUT ;
    USE SIGNAL ;
    PORT
      LAYER M5 ;
        RECT  16.992 0 17.016 0.192 ;
    END
  END dr_o[109]
  PIN dr_o[10]
    DIRECTION OUTPUT ;
    USE SIGNAL ;
    PORT
      LAYER M5 ;
        RECT  7.488 0 7.512 0.192 ;
    END
  END dr_o[10]
  PIN dr_o[110]
    DIRECTION OUTPUT ;
    USE SIGNAL ;
    PORT
      LAYER M5 ;
        RECT  17.088 0 17.112 0.192 ;
    END
  END dr_o[110]
  PIN dr_o[111]
    DIRECTION OUTPUT ;
    USE SIGNAL ;
    PORT
      LAYER M5 ;
        RECT  17.184 0 17.208 0.192 ;
    END
  END dr_o[111]
  PIN dr_o[112]
    DIRECTION OUTPUT ;
    USE SIGNAL ;
    PORT
      LAYER M5 ;
        RECT  17.28 0 17.304 0.192 ;
    END
  END dr_o[112]
  PIN dr_o[113]
    DIRECTION OUTPUT ;
    USE SIGNAL ;
    PORT
      LAYER M5 ;
        RECT  17.376 0 17.4 0.192 ;
    END
  END dr_o[113]
  PIN dr_o[114]
    DIRECTION OUTPUT ;
    USE SIGNAL ;
    PORT
      LAYER M5 ;
        RECT  17.472 0 17.496 0.192 ;
    END
  END dr_o[114]
  PIN dr_o[115]
    DIRECTION OUTPUT ;
    USE SIGNAL ;
    PORT
      LAYER M5 ;
        RECT  17.568 0 17.592 0.192 ;
    END
  END dr_o[115]
  PIN dr_o[116]
    DIRECTION OUTPUT ;
    USE SIGNAL ;
    PORT
      LAYER M5 ;
        RECT  17.664 0 17.688 0.192 ;
    END
  END dr_o[116]
  PIN dr_o[117]
    DIRECTION OUTPUT ;
    USE SIGNAL ;
    PORT
      LAYER M5 ;
        RECT  17.76 0 17.784 0.192 ;
    END
  END dr_o[117]
  PIN dr_o[118]
    DIRECTION OUTPUT ;
    USE SIGNAL ;
    PORT
      LAYER M5 ;
        RECT  17.856 0 17.88 0.192 ;
    END
  END dr_o[118]
  PIN dr_o[119]
    DIRECTION OUTPUT ;
    USE SIGNAL ;
    PORT
      LAYER M5 ;
        RECT  17.952 0 17.976 0.192 ;
    END
  END dr_o[119]
  PIN dr_o[11]
    DIRECTION OUTPUT ;
    USE SIGNAL ;
    PORT
      LAYER M5 ;
        RECT  7.584 0 7.608 0.192 ;
    END
  END dr_o[11]
  PIN dr_o[120]
    DIRECTION OUTPUT ;
    USE SIGNAL ;
    PORT
      LAYER M5 ;
        RECT  18.048 0 18.072 0.192 ;
    END
  END dr_o[120]
  PIN dr_o[121]
    DIRECTION OUTPUT ;
    USE SIGNAL ;
    PORT
      LAYER M5 ;
        RECT  18.144 0 18.168 0.192 ;
    END
  END dr_o[121]
  PIN dr_o[122]
    DIRECTION OUTPUT ;
    USE SIGNAL ;
    PORT
      LAYER M5 ;
        RECT  18.24 0 18.264 0.192 ;
    END
  END dr_o[122]
  PIN dr_o[123]
    DIRECTION OUTPUT ;
    USE SIGNAL ;
    PORT
      LAYER M5 ;
        RECT  18.336 0 18.36 0.192 ;
    END
  END dr_o[123]
  PIN dr_o[124]
    DIRECTION OUTPUT ;
    USE SIGNAL ;
    PORT
      LAYER M5 ;
        RECT  18.432 0 18.456 0.192 ;
    END
  END dr_o[124]
  PIN dr_o[125]
    DIRECTION OUTPUT ;
    USE SIGNAL ;
    PORT
      LAYER M5 ;
        RECT  18.528 0 18.552 0.192 ;
    END
  END dr_o[125]
  PIN dr_o[126]
    DIRECTION OUTPUT ;
    USE SIGNAL ;
    PORT
      LAYER M5 ;
        RECT  18.624 0 18.648 0.192 ;
    END
  END dr_o[126]
  PIN dr_o[127]
    DIRECTION OUTPUT ;
    USE SIGNAL ;
    PORT
      LAYER M5 ;
        RECT  18.72 0 18.744 0.192 ;
    END
  END dr_o[127]
  PIN dr_o[128]
    DIRECTION OUTPUT ;
    USE SIGNAL ;
    PORT
      LAYER M5 ;
        RECT  18.816 0 18.84 0.192 ;
    END
  END dr_o[128]
  PIN dr_o[129]
    DIRECTION OUTPUT ;
    USE SIGNAL ;
    PORT
      LAYER M5 ;
        RECT  18.912 0 18.936 0.192 ;
    END
  END dr_o[129]
  PIN dr_o[12]
    DIRECTION OUTPUT ;
    USE SIGNAL ;
    PORT
      LAYER M5 ;
        RECT  7.68 0 7.704 0.192 ;
    END
  END dr_o[12]
  PIN dr_o[130]
    DIRECTION OUTPUT ;
    USE SIGNAL ;
    PORT
      LAYER M5 ;
        RECT  19.008 0 19.032 0.192 ;
    END
  END dr_o[130]
  PIN dr_o[131]
    DIRECTION OUTPUT ;
    USE SIGNAL ;
    PORT
      LAYER M5 ;
        RECT  19.104 0 19.128 0.192 ;
    END
  END dr_o[131]
  PIN dr_o[132]
    DIRECTION OUTPUT ;
    USE SIGNAL ;
    PORT
      LAYER M5 ;
        RECT  19.2 0 19.224 0.192 ;
    END
  END dr_o[132]
  PIN dr_o[133]
    DIRECTION OUTPUT ;
    USE SIGNAL ;
    PORT
      LAYER M5 ;
        RECT  19.296 0 19.32 0.192 ;
    END
  END dr_o[133]
  PIN dr_o[134]
    DIRECTION OUTPUT ;
    USE SIGNAL ;
    PORT
      LAYER M5 ;
        RECT  19.392 0 19.416 0.192 ;
    END
  END dr_o[134]
  PIN dr_o[135]
    DIRECTION OUTPUT ;
    USE SIGNAL ;
    PORT
      LAYER M5 ;
        RECT  19.488 0 19.512 0.192 ;
    END
  END dr_o[135]
  PIN dr_o[136]
    DIRECTION OUTPUT ;
    USE SIGNAL ;
    PORT
      LAYER M5 ;
        RECT  19.584 0 19.608 0.192 ;
    END
  END dr_o[136]
  PIN dr_o[137]
    DIRECTION OUTPUT ;
    USE SIGNAL ;
    PORT
      LAYER M5 ;
        RECT  19.68 0 19.704 0.192 ;
    END
  END dr_o[137]
  PIN dr_o[138]
    DIRECTION OUTPUT ;
    USE SIGNAL ;
    PORT
      LAYER M5 ;
        RECT  19.776 0 19.8 0.192 ;
    END
  END dr_o[138]
  PIN dr_o[139]
    DIRECTION OUTPUT ;
    USE SIGNAL ;
    PORT
      LAYER M5 ;
        RECT  19.872 0 19.896 0.192 ;
    END
  END dr_o[139]
  PIN dr_o[13]
    DIRECTION OUTPUT ;
    USE SIGNAL ;
    PORT
      LAYER M5 ;
        RECT  7.776 0 7.8 0.192 ;
    END
  END dr_o[13]
  PIN dr_o[140]
    DIRECTION OUTPUT ;
    USE SIGNAL ;
    PORT
      LAYER M5 ;
        RECT  19.968 0 19.992 0.192 ;
    END
  END dr_o[140]
  PIN dr_o[141]
    DIRECTION OUTPUT ;
    USE SIGNAL ;
    PORT
      LAYER M5 ;
        RECT  20.064 0 20.088 0.192 ;
    END
  END dr_o[141]
  PIN dr_o[142]
    DIRECTION OUTPUT ;
    USE SIGNAL ;
    PORT
      LAYER M5 ;
        RECT  20.16 0 20.184 0.192 ;
    END
  END dr_o[142]
  PIN dr_o[143]
    DIRECTION OUTPUT ;
    USE SIGNAL ;
    PORT
      LAYER M5 ;
        RECT  20.256 0 20.28 0.192 ;
    END
  END dr_o[143]
  PIN dr_o[144]
    DIRECTION OUTPUT ;
    USE SIGNAL ;
    PORT
      LAYER M5 ;
        RECT  20.352 0 20.376 0.192 ;
    END
  END dr_o[144]
  PIN dr_o[145]
    DIRECTION OUTPUT ;
    USE SIGNAL ;
    PORT
      LAYER M5 ;
        RECT  20.448 0 20.472 0.192 ;
    END
  END dr_o[145]
  PIN dr_o[146]
    DIRECTION OUTPUT ;
    USE SIGNAL ;
    PORT
      LAYER M5 ;
        RECT  20.544 0 20.568 0.192 ;
    END
  END dr_o[146]
  PIN dr_o[147]
    DIRECTION OUTPUT ;
    USE SIGNAL ;
    PORT
      LAYER M5 ;
        RECT  20.64 0 20.664 0.192 ;
    END
  END dr_o[147]
  PIN dr_o[148]
    DIRECTION OUTPUT ;
    USE SIGNAL ;
    PORT
      LAYER M5 ;
        RECT  20.736 0 20.76 0.192 ;
    END
  END dr_o[148]
  PIN dr_o[149]
    DIRECTION OUTPUT ;
    USE SIGNAL ;
    PORT
      LAYER M5 ;
        RECT  20.832 0 20.856 0.192 ;
    END
  END dr_o[149]
  PIN dr_o[14]
    DIRECTION OUTPUT ;
    USE SIGNAL ;
    PORT
      LAYER M5 ;
        RECT  7.872 0 7.896 0.192 ;
    END
  END dr_o[14]
  PIN dr_o[150]
    DIRECTION OUTPUT ;
    USE SIGNAL ;
    PORT
      LAYER M5 ;
        RECT  20.928 0 20.952 0.192 ;
    END
  END dr_o[150]
  PIN dr_o[151]
    DIRECTION OUTPUT ;
    USE SIGNAL ;
    PORT
      LAYER M5 ;
        RECT  21.024 0 21.048 0.192 ;
    END
  END dr_o[151]
  PIN dr_o[152]
    DIRECTION OUTPUT ;
    USE SIGNAL ;
    PORT
      LAYER M5 ;
        RECT  21.12 0 21.144 0.192 ;
    END
  END dr_o[152]
  PIN dr_o[153]
    DIRECTION OUTPUT ;
    USE SIGNAL ;
    PORT
      LAYER M5 ;
        RECT  21.216 0 21.24 0.192 ;
    END
  END dr_o[153]
  PIN dr_o[154]
    DIRECTION OUTPUT ;
    USE SIGNAL ;
    PORT
      LAYER M5 ;
        RECT  21.312 0 21.336 0.192 ;
    END
  END dr_o[154]
  PIN dr_o[155]
    DIRECTION OUTPUT ;
    USE SIGNAL ;
    PORT
      LAYER M5 ;
        RECT  21.408 0 21.432 0.192 ;
    END
  END dr_o[155]
  PIN dr_o[156]
    DIRECTION OUTPUT ;
    USE SIGNAL ;
    PORT
      LAYER M5 ;
        RECT  21.504 0 21.528 0.192 ;
    END
  END dr_o[156]
  PIN dr_o[157]
    DIRECTION OUTPUT ;
    USE SIGNAL ;
    PORT
      LAYER M5 ;
        RECT  21.6 0 21.624 0.192 ;
    END
  END dr_o[157]
  PIN dr_o[158]
    DIRECTION OUTPUT ;
    USE SIGNAL ;
    PORT
      LAYER M5 ;
        RECT  21.696 0 21.72 0.192 ;
    END
  END dr_o[158]
  PIN dr_o[159]
    DIRECTION OUTPUT ;
    USE SIGNAL ;
    PORT
      LAYER M5 ;
        RECT  21.792 0 21.816 0.192 ;
    END
  END dr_o[159]
  PIN dr_o[15]
    DIRECTION OUTPUT ;
    USE SIGNAL ;
    PORT
      LAYER M5 ;
        RECT  7.968 0 7.992 0.192 ;
    END
  END dr_o[15]
  PIN dr_o[160]
    DIRECTION OUTPUT ;
    USE SIGNAL ;
    PORT
      LAYER M5 ;
        RECT  21.888 0 21.912 0.192 ;
    END
  END dr_o[160]
  PIN dr_o[161]
    DIRECTION OUTPUT ;
    USE SIGNAL ;
    PORT
      LAYER M5 ;
        RECT  21.984 0 22.008 0.192 ;
    END
  END dr_o[161]
  PIN dr_o[162]
    DIRECTION OUTPUT ;
    USE SIGNAL ;
    PORT
      LAYER M5 ;
        RECT  22.08 0 22.104 0.192 ;
    END
  END dr_o[162]
  PIN dr_o[163]
    DIRECTION OUTPUT ;
    USE SIGNAL ;
    PORT
      LAYER M5 ;
        RECT  22.176 0 22.2 0.192 ;
    END
  END dr_o[163]
  PIN dr_o[164]
    DIRECTION OUTPUT ;
    USE SIGNAL ;
    PORT
      LAYER M5 ;
        RECT  22.272 0 22.296 0.192 ;
    END
  END dr_o[164]
  PIN dr_o[165]
    DIRECTION OUTPUT ;
    USE SIGNAL ;
    PORT
      LAYER M5 ;
        RECT  22.368 0 22.392 0.192 ;
    END
  END dr_o[165]
  PIN dr_o[166]
    DIRECTION OUTPUT ;
    USE SIGNAL ;
    PORT
      LAYER M5 ;
        RECT  22.464 0 22.488 0.192 ;
    END
  END dr_o[166]
  PIN dr_o[167]
    DIRECTION OUTPUT ;
    USE SIGNAL ;
    PORT
      LAYER M5 ;
        RECT  22.56 0 22.584 0.192 ;
    END
  END dr_o[167]
  PIN dr_o[168]
    DIRECTION OUTPUT ;
    USE SIGNAL ;
    PORT
      LAYER M5 ;
        RECT  22.656 0 22.68 0.192 ;
    END
  END dr_o[168]
  PIN dr_o[169]
    DIRECTION OUTPUT ;
    USE SIGNAL ;
    PORT
      LAYER M5 ;
        RECT  22.752 0 22.776 0.192 ;
    END
  END dr_o[169]
  PIN dr_o[16]
    DIRECTION OUTPUT ;
    USE SIGNAL ;
    PORT
      LAYER M5 ;
        RECT  8.064 0 8.088 0.192 ;
    END
  END dr_o[16]
  PIN dr_o[170]
    DIRECTION OUTPUT ;
    USE SIGNAL ;
    PORT
      LAYER M5 ;
        RECT  22.848 0 22.872 0.192 ;
    END
  END dr_o[170]
  PIN dr_o[171]
    DIRECTION OUTPUT ;
    USE SIGNAL ;
    PORT
      LAYER M5 ;
        RECT  22.944 0 22.968 0.192 ;
    END
  END dr_o[171]
  PIN dr_o[172]
    DIRECTION OUTPUT ;
    USE SIGNAL ;
    PORT
      LAYER M5 ;
        RECT  23.04 0 23.064 0.192 ;
    END
  END dr_o[172]
  PIN dr_o[173]
    DIRECTION OUTPUT ;
    USE SIGNAL ;
    PORT
      LAYER M5 ;
        RECT  23.136 0 23.16 0.192 ;
    END
  END dr_o[173]
  PIN dr_o[174]
    DIRECTION OUTPUT ;
    USE SIGNAL ;
    PORT
      LAYER M5 ;
        RECT  23.232 0 23.256 0.192 ;
    END
  END dr_o[174]
  PIN dr_o[175]
    DIRECTION OUTPUT ;
    USE SIGNAL ;
    PORT
      LAYER M5 ;
        RECT  23.328 0 23.352 0.192 ;
    END
  END dr_o[175]
  PIN dr_o[176]
    DIRECTION OUTPUT ;
    USE SIGNAL ;
    PORT
      LAYER M5 ;
        RECT  23.424 0 23.448 0.192 ;
    END
  END dr_o[176]
  PIN dr_o[177]
    DIRECTION OUTPUT ;
    USE SIGNAL ;
    PORT
      LAYER M5 ;
        RECT  23.52 0 23.544 0.192 ;
    END
  END dr_o[177]
  PIN dr_o[178]
    DIRECTION OUTPUT ;
    USE SIGNAL ;
    PORT
      LAYER M5 ;
        RECT  23.616 0 23.64 0.192 ;
    END
  END dr_o[178]
  PIN dr_o[179]
    DIRECTION OUTPUT ;
    USE SIGNAL ;
    PORT
      LAYER M5 ;
        RECT  23.712 0 23.736 0.192 ;
    END
  END dr_o[179]
  PIN dr_o[17]
    DIRECTION OUTPUT ;
    USE SIGNAL ;
    PORT
      LAYER M5 ;
        RECT  8.16 0 8.184 0.192 ;
    END
  END dr_o[17]
  PIN dr_o[180]
    DIRECTION OUTPUT ;
    USE SIGNAL ;
    PORT
      LAYER M5 ;
        RECT  23.808 0 23.832 0.192 ;
    END
  END dr_o[180]
  PIN dr_o[181]
    DIRECTION OUTPUT ;
    USE SIGNAL ;
    PORT
      LAYER M5 ;
        RECT  23.904 0 23.928 0.192 ;
    END
  END dr_o[181]
  PIN dr_o[182]
    DIRECTION OUTPUT ;
    USE SIGNAL ;
    PORT
      LAYER M5 ;
        RECT  24 0 24.024 0.192 ;
    END
  END dr_o[182]
  PIN dr_o[183]
    DIRECTION OUTPUT ;
    USE SIGNAL ;
    PORT
      LAYER M5 ;
        RECT  24.096 0 24.12 0.192 ;
    END
  END dr_o[183]
  PIN dr_o[184]
    DIRECTION OUTPUT ;
    USE SIGNAL ;
    PORT
      LAYER M5 ;
        RECT  24.192 0 24.216 0.192 ;
    END
  END dr_o[184]
  PIN dr_o[185]
    DIRECTION OUTPUT ;
    USE SIGNAL ;
    PORT
      LAYER M5 ;
        RECT  24.288 0 24.312 0.192 ;
    END
  END dr_o[185]
  PIN dr_o[186]
    DIRECTION OUTPUT ;
    USE SIGNAL ;
    PORT
      LAYER M5 ;
        RECT  24.384 0 24.408 0.192 ;
    END
  END dr_o[186]
  PIN dr_o[187]
    DIRECTION OUTPUT ;
    USE SIGNAL ;
    PORT
      LAYER M5 ;
        RECT  24.48 0 24.504 0.192 ;
    END
  END dr_o[187]
  PIN dr_o[188]
    DIRECTION OUTPUT ;
    USE SIGNAL ;
    PORT
      LAYER M5 ;
        RECT  24.576 0 24.6 0.192 ;
    END
  END dr_o[188]
  PIN dr_o[189]
    DIRECTION OUTPUT ;
    USE SIGNAL ;
    PORT
      LAYER M5 ;
        RECT  24.672 0 24.696 0.192 ;
    END
  END dr_o[189]
  PIN dr_o[18]
    DIRECTION OUTPUT ;
    USE SIGNAL ;
    PORT
      LAYER M5 ;
        RECT  8.256 0 8.28 0.192 ;
    END
  END dr_o[18]
  PIN dr_o[190]
    DIRECTION OUTPUT ;
    USE SIGNAL ;
    PORT
      LAYER M5 ;
        RECT  24.768 0 24.792 0.192 ;
    END
  END dr_o[190]
  PIN dr_o[191]
    DIRECTION OUTPUT ;
    USE SIGNAL ;
    PORT
      LAYER M5 ;
        RECT  24.864 0 24.888 0.192 ;
    END
  END dr_o[191]
  PIN dr_o[192]
    DIRECTION OUTPUT ;
    USE SIGNAL ;
    PORT
      LAYER M5 ;
        RECT  24.96 0 24.984 0.192 ;
    END
  END dr_o[192]
  PIN dr_o[193]
    DIRECTION OUTPUT ;
    USE SIGNAL ;
    PORT
      LAYER M5 ;
        RECT  25.056 0 25.08 0.192 ;
    END
  END dr_o[193]
  PIN dr_o[194]
    DIRECTION OUTPUT ;
    USE SIGNAL ;
    PORT
      LAYER M5 ;
        RECT  25.152 0 25.176 0.192 ;
    END
  END dr_o[194]
  PIN dr_o[195]
    DIRECTION OUTPUT ;
    USE SIGNAL ;
    PORT
      LAYER M5 ;
        RECT  25.248 0 25.272 0.192 ;
    END
  END dr_o[195]
  PIN dr_o[196]
    DIRECTION OUTPUT ;
    USE SIGNAL ;
    PORT
      LAYER M5 ;
        RECT  25.344 0 25.368 0.192 ;
    END
  END dr_o[196]
  PIN dr_o[197]
    DIRECTION OUTPUT ;
    USE SIGNAL ;
    PORT
      LAYER M5 ;
        RECT  25.44 0 25.464 0.192 ;
    END
  END dr_o[197]
  PIN dr_o[198]
    DIRECTION OUTPUT ;
    USE SIGNAL ;
    PORT
      LAYER M5 ;
        RECT  25.536 0 25.56 0.192 ;
    END
  END dr_o[198]
  PIN dr_o[199]
    DIRECTION OUTPUT ;
    USE SIGNAL ;
    PORT
      LAYER M5 ;
        RECT  25.632 0 25.656 0.192 ;
    END
  END dr_o[199]
  PIN dr_o[19]
    DIRECTION OUTPUT ;
    USE SIGNAL ;
    PORT
      LAYER M5 ;
        RECT  8.352 0 8.376 0.192 ;
    END
  END dr_o[19]
  PIN dr_o[1]
    DIRECTION OUTPUT ;
    USE SIGNAL ;
    PORT
      LAYER M5 ;
        RECT  6.624 0 6.648 0.192 ;
    END
  END dr_o[1]
  PIN dr_o[200]
    DIRECTION OUTPUT ;
    USE SIGNAL ;
    PORT
      LAYER M5 ;
        RECT  25.728 0 25.752 0.192 ;
    END
  END dr_o[200]
  PIN dr_o[201]
    DIRECTION OUTPUT ;
    USE SIGNAL ;
    PORT
      LAYER M5 ;
        RECT  25.824 0 25.848 0.192 ;
    END
  END dr_o[201]
  PIN dr_o[202]
    DIRECTION OUTPUT ;
    USE SIGNAL ;
    PORT
      LAYER M5 ;
        RECT  25.92 0 25.944 0.192 ;
    END
  END dr_o[202]
  PIN dr_o[203]
    DIRECTION OUTPUT ;
    USE SIGNAL ;
    PORT
      LAYER M5 ;
        RECT  26.016 0 26.04 0.192 ;
    END
  END dr_o[203]
  PIN dr_o[204]
    DIRECTION OUTPUT ;
    USE SIGNAL ;
    PORT
      LAYER M5 ;
        RECT  26.112 0 26.136 0.192 ;
    END
  END dr_o[204]
  PIN dr_o[205]
    DIRECTION OUTPUT ;
    USE SIGNAL ;
    PORT
      LAYER M5 ;
        RECT  26.208 0 26.232 0.192 ;
    END
  END dr_o[205]
  PIN dr_o[206]
    DIRECTION OUTPUT ;
    USE SIGNAL ;
    PORT
      LAYER M5 ;
        RECT  26.304 0 26.328 0.192 ;
    END
  END dr_o[206]
  PIN dr_o[207]
    DIRECTION OUTPUT ;
    USE SIGNAL ;
    PORT
      LAYER M5 ;
        RECT  26.4 0 26.424 0.192 ;
    END
  END dr_o[207]
  PIN dr_o[208]
    DIRECTION OUTPUT ;
    USE SIGNAL ;
    PORT
      LAYER M5 ;
        RECT  26.496 0 26.52 0.192 ;
    END
  END dr_o[208]
  PIN dr_o[209]
    DIRECTION OUTPUT ;
    USE SIGNAL ;
    PORT
      LAYER M5 ;
        RECT  26.592 0 26.616 0.192 ;
    END
  END dr_o[209]
  PIN dr_o[20]
    DIRECTION OUTPUT ;
    USE SIGNAL ;
    PORT
      LAYER M5 ;
        RECT  8.448 0 8.472 0.192 ;
    END
  END dr_o[20]
  PIN dr_o[210]
    DIRECTION OUTPUT ;
    USE SIGNAL ;
    PORT
      LAYER M5 ;
        RECT  26.688 0 26.712 0.192 ;
    END
  END dr_o[210]
  PIN dr_o[211]
    DIRECTION OUTPUT ;
    USE SIGNAL ;
    PORT
      LAYER M5 ;
        RECT  26.784 0 26.808 0.192 ;
    END
  END dr_o[211]
  PIN dr_o[212]
    DIRECTION OUTPUT ;
    USE SIGNAL ;
    PORT
      LAYER M5 ;
        RECT  26.88 0 26.904 0.192 ;
    END
  END dr_o[212]
  PIN dr_o[213]
    DIRECTION OUTPUT ;
    USE SIGNAL ;
    PORT
      LAYER M5 ;
        RECT  26.976 0 27 0.192 ;
    END
  END dr_o[213]
  PIN dr_o[214]
    DIRECTION OUTPUT ;
    USE SIGNAL ;
    PORT
      LAYER M5 ;
        RECT  27.072 0 27.096 0.192 ;
    END
  END dr_o[214]
  PIN dr_o[215]
    DIRECTION OUTPUT ;
    USE SIGNAL ;
    PORT
      LAYER M5 ;
        RECT  27.168 0 27.192 0.192 ;
    END
  END dr_o[215]
  PIN dr_o[216]
    DIRECTION OUTPUT ;
    USE SIGNAL ;
    PORT
      LAYER M5 ;
        RECT  27.264 0 27.288 0.192 ;
    END
  END dr_o[216]
  PIN dr_o[21]
    DIRECTION OUTPUT ;
    USE SIGNAL ;
    PORT
      LAYER M5 ;
        RECT  8.544 0 8.568 0.192 ;
    END
  END dr_o[21]
  PIN dr_o[22]
    DIRECTION OUTPUT ;
    USE SIGNAL ;
    PORT
      LAYER M5 ;
        RECT  8.64 0 8.664 0.192 ;
    END
  END dr_o[22]
  PIN dr_o[23]
    DIRECTION OUTPUT ;
    USE SIGNAL ;
    PORT
      LAYER M5 ;
        RECT  8.736 0 8.76 0.192 ;
    END
  END dr_o[23]
  PIN dr_o[24]
    DIRECTION OUTPUT ;
    USE SIGNAL ;
    PORT
      LAYER M5 ;
        RECT  8.832 0 8.856 0.192 ;
    END
  END dr_o[24]
  PIN dr_o[25]
    DIRECTION OUTPUT ;
    USE SIGNAL ;
    PORT
      LAYER M5 ;
        RECT  8.928 0 8.952 0.192 ;
    END
  END dr_o[25]
  PIN dr_o[26]
    DIRECTION OUTPUT ;
    USE SIGNAL ;
    PORT
      LAYER M5 ;
        RECT  9.024 0 9.048 0.192 ;
    END
  END dr_o[26]
  PIN dr_o[27]
    DIRECTION OUTPUT ;
    USE SIGNAL ;
    PORT
      LAYER M5 ;
        RECT  9.12 0 9.144 0.192 ;
    END
  END dr_o[27]
  PIN dr_o[28]
    DIRECTION OUTPUT ;
    USE SIGNAL ;
    PORT
      LAYER M5 ;
        RECT  9.216 0 9.24 0.192 ;
    END
  END dr_o[28]
  PIN dr_o[29]
    DIRECTION OUTPUT ;
    USE SIGNAL ;
    PORT
      LAYER M5 ;
        RECT  9.312 0 9.336 0.192 ;
    END
  END dr_o[29]
  PIN dr_o[2]
    DIRECTION OUTPUT ;
    USE SIGNAL ;
    PORT
      LAYER M5 ;
        RECT  6.72 0 6.744 0.192 ;
    END
  END dr_o[2]
  PIN dr_o[30]
    DIRECTION OUTPUT ;
    USE SIGNAL ;
    PORT
      LAYER M5 ;
        RECT  9.408 0 9.432 0.192 ;
    END
  END dr_o[30]
  PIN dr_o[31]
    DIRECTION OUTPUT ;
    USE SIGNAL ;
    PORT
      LAYER M5 ;
        RECT  9.504 0 9.528 0.192 ;
    END
  END dr_o[31]
  PIN dr_o[32]
    DIRECTION OUTPUT ;
    USE SIGNAL ;
    PORT
      LAYER M5 ;
        RECT  9.6 0 9.624 0.192 ;
    END
  END dr_o[32]
  PIN dr_o[33]
    DIRECTION OUTPUT ;
    USE SIGNAL ;
    PORT
      LAYER M5 ;
        RECT  9.696 0 9.72 0.192 ;
    END
  END dr_o[33]
  PIN dr_o[34]
    DIRECTION OUTPUT ;
    USE SIGNAL ;
    PORT
      LAYER M5 ;
        RECT  9.792 0 9.816 0.192 ;
    END
  END dr_o[34]
  PIN dr_o[35]
    DIRECTION OUTPUT ;
    USE SIGNAL ;
    PORT
      LAYER M5 ;
        RECT  9.888 0 9.912 0.192 ;
    END
  END dr_o[35]
  PIN dr_o[36]
    DIRECTION OUTPUT ;
    USE SIGNAL ;
    PORT
      LAYER M5 ;
        RECT  9.984 0 10.008 0.192 ;
    END
  END dr_o[36]
  PIN dr_o[37]
    DIRECTION OUTPUT ;
    USE SIGNAL ;
    PORT
      LAYER M5 ;
        RECT  10.08 0 10.104 0.192 ;
    END
  END dr_o[37]
  PIN dr_o[38]
    DIRECTION OUTPUT ;
    USE SIGNAL ;
    PORT
      LAYER M5 ;
        RECT  10.176 0 10.2 0.192 ;
    END
  END dr_o[38]
  PIN dr_o[39]
    DIRECTION OUTPUT ;
    USE SIGNAL ;
    PORT
      LAYER M5 ;
        RECT  10.272 0 10.296 0.192 ;
    END
  END dr_o[39]
  PIN dr_o[3]
    DIRECTION OUTPUT ;
    USE SIGNAL ;
    PORT
      LAYER M5 ;
        RECT  6.816 0 6.84 0.192 ;
    END
  END dr_o[3]
  PIN dr_o[40]
    DIRECTION OUTPUT ;
    USE SIGNAL ;
    PORT
      LAYER M5 ;
        RECT  10.368 0 10.392 0.192 ;
    END
  END dr_o[40]
  PIN dr_o[41]
    DIRECTION OUTPUT ;
    USE SIGNAL ;
    PORT
      LAYER M5 ;
        RECT  10.464 0 10.488 0.192 ;
    END
  END dr_o[41]
  PIN dr_o[42]
    DIRECTION OUTPUT ;
    USE SIGNAL ;
    PORT
      LAYER M5 ;
        RECT  10.56 0 10.584 0.192 ;
    END
  END dr_o[42]
  PIN dr_o[43]
    DIRECTION OUTPUT ;
    USE SIGNAL ;
    PORT
      LAYER M5 ;
        RECT  10.656 0 10.68 0.192 ;
    END
  END dr_o[43]
  PIN dr_o[44]
    DIRECTION OUTPUT ;
    USE SIGNAL ;
    PORT
      LAYER M5 ;
        RECT  10.752 0 10.776 0.192 ;
    END
  END dr_o[44]
  PIN dr_o[45]
    DIRECTION OUTPUT ;
    USE SIGNAL ;
    PORT
      LAYER M5 ;
        RECT  10.848 0 10.872 0.192 ;
    END
  END dr_o[45]
  PIN dr_o[46]
    DIRECTION OUTPUT ;
    USE SIGNAL ;
    PORT
      LAYER M5 ;
        RECT  10.944 0 10.968 0.192 ;
    END
  END dr_o[46]
  PIN dr_o[47]
    DIRECTION OUTPUT ;
    USE SIGNAL ;
    PORT
      LAYER M5 ;
        RECT  11.04 0 11.064 0.192 ;
    END
  END dr_o[47]
  PIN dr_o[48]
    DIRECTION OUTPUT ;
    USE SIGNAL ;
    PORT
      LAYER M5 ;
        RECT  11.136 0 11.16 0.192 ;
    END
  END dr_o[48]
  PIN dr_o[49]
    DIRECTION OUTPUT ;
    USE SIGNAL ;
    PORT
      LAYER M5 ;
        RECT  11.232 0 11.256 0.192 ;
    END
  END dr_o[49]
  PIN dr_o[4]
    DIRECTION OUTPUT ;
    USE SIGNAL ;
    PORT
      LAYER M5 ;
        RECT  6.912 0 6.936 0.192 ;
    END
  END dr_o[4]
  PIN dr_o[50]
    DIRECTION OUTPUT ;
    USE SIGNAL ;
    PORT
      LAYER M5 ;
        RECT  11.328 0 11.352 0.192 ;
    END
  END dr_o[50]
  PIN dr_o[51]
    DIRECTION OUTPUT ;
    USE SIGNAL ;
    PORT
      LAYER M5 ;
        RECT  11.424 0 11.448 0.192 ;
    END
  END dr_o[51]
  PIN dr_o[52]
    DIRECTION OUTPUT ;
    USE SIGNAL ;
    PORT
      LAYER M5 ;
        RECT  11.52 0 11.544 0.192 ;
    END
  END dr_o[52]
  PIN dr_o[53]
    DIRECTION OUTPUT ;
    USE SIGNAL ;
    PORT
      LAYER M5 ;
        RECT  11.616 0 11.64 0.192 ;
    END
  END dr_o[53]
  PIN dr_o[54]
    DIRECTION OUTPUT ;
    USE SIGNAL ;
    PORT
      LAYER M5 ;
        RECT  11.712 0 11.736 0.192 ;
    END
  END dr_o[54]
  PIN dr_o[55]
    DIRECTION OUTPUT ;
    USE SIGNAL ;
    PORT
      LAYER M5 ;
        RECT  11.808 0 11.832 0.192 ;
    END
  END dr_o[55]
  PIN dr_o[56]
    DIRECTION OUTPUT ;
    USE SIGNAL ;
    PORT
      LAYER M5 ;
        RECT  11.904 0 11.928 0.192 ;
    END
  END dr_o[56]
  PIN dr_o[57]
    DIRECTION OUTPUT ;
    USE SIGNAL ;
    PORT
      LAYER M5 ;
        RECT  12 0 12.024 0.192 ;
    END
  END dr_o[57]
  PIN dr_o[58]
    DIRECTION OUTPUT ;
    USE SIGNAL ;
    PORT
      LAYER M5 ;
        RECT  12.096 0 12.12 0.192 ;
    END
  END dr_o[58]
  PIN dr_o[59]
    DIRECTION OUTPUT ;
    USE SIGNAL ;
    PORT
      LAYER M5 ;
        RECT  12.192 0 12.216 0.192 ;
    END
  END dr_o[59]
  PIN dr_o[5]
    DIRECTION OUTPUT ;
    USE SIGNAL ;
    PORT
      LAYER M5 ;
        RECT  7.008 0 7.032 0.192 ;
    END
  END dr_o[5]
  PIN dr_o[60]
    DIRECTION OUTPUT ;
    USE SIGNAL ;
    PORT
      LAYER M5 ;
        RECT  12.288 0 12.312 0.192 ;
    END
  END dr_o[60]
  PIN dr_o[61]
    DIRECTION OUTPUT ;
    USE SIGNAL ;
    PORT
      LAYER M5 ;
        RECT  12.384 0 12.408 0.192 ;
    END
  END dr_o[61]
  PIN dr_o[62]
    DIRECTION OUTPUT ;
    USE SIGNAL ;
    PORT
      LAYER M5 ;
        RECT  12.48 0 12.504 0.192 ;
    END
  END dr_o[62]
  PIN dr_o[63]
    DIRECTION OUTPUT ;
    USE SIGNAL ;
    PORT
      LAYER M5 ;
        RECT  12.576 0 12.6 0.192 ;
    END
  END dr_o[63]
  PIN dr_o[64]
    DIRECTION OUTPUT ;
    USE SIGNAL ;
    PORT
      LAYER M5 ;
        RECT  12.672 0 12.696 0.192 ;
    END
  END dr_o[64]
  PIN dr_o[65]
    DIRECTION OUTPUT ;
    USE SIGNAL ;
    PORT
      LAYER M5 ;
        RECT  12.768 0 12.792 0.192 ;
    END
  END dr_o[65]
  PIN dr_o[66]
    DIRECTION OUTPUT ;
    USE SIGNAL ;
    PORT
      LAYER M5 ;
        RECT  12.864 0 12.888 0.192 ;
    END
  END dr_o[66]
  PIN dr_o[67]
    DIRECTION OUTPUT ;
    USE SIGNAL ;
    PORT
      LAYER M5 ;
        RECT  12.96 0 12.984 0.192 ;
    END
  END dr_o[67]
  PIN dr_o[68]
    DIRECTION OUTPUT ;
    USE SIGNAL ;
    PORT
      LAYER M5 ;
        RECT  13.056 0 13.08 0.192 ;
    END
  END dr_o[68]
  PIN dr_o[69]
    DIRECTION OUTPUT ;
    USE SIGNAL ;
    PORT
      LAYER M5 ;
        RECT  13.152 0 13.176 0.192 ;
    END
  END dr_o[69]
  PIN dr_o[6]
    DIRECTION OUTPUT ;
    USE SIGNAL ;
    PORT
      LAYER M5 ;
        RECT  7.104 0 7.128 0.192 ;
    END
  END dr_o[6]
  PIN dr_o[70]
    DIRECTION OUTPUT ;
    USE SIGNAL ;
    PORT
      LAYER M5 ;
        RECT  13.248 0 13.272 0.192 ;
    END
  END dr_o[70]
  PIN dr_o[71]
    DIRECTION OUTPUT ;
    USE SIGNAL ;
    PORT
      LAYER M5 ;
        RECT  13.344 0 13.368 0.192 ;
    END
  END dr_o[71]
  PIN dr_o[72]
    DIRECTION OUTPUT ;
    USE SIGNAL ;
    PORT
      LAYER M5 ;
        RECT  13.44 0 13.464 0.192 ;
    END
  END dr_o[72]
  PIN dr_o[73]
    DIRECTION OUTPUT ;
    USE SIGNAL ;
    PORT
      LAYER M5 ;
        RECT  13.536 0 13.56 0.192 ;
    END
  END dr_o[73]
  PIN dr_o[74]
    DIRECTION OUTPUT ;
    USE SIGNAL ;
    PORT
      LAYER M5 ;
        RECT  13.632 0 13.656 0.192 ;
    END
  END dr_o[74]
  PIN dr_o[75]
    DIRECTION OUTPUT ;
    USE SIGNAL ;
    PORT
      LAYER M5 ;
        RECT  13.728 0 13.752 0.192 ;
    END
  END dr_o[75]
  PIN dr_o[76]
    DIRECTION OUTPUT ;
    USE SIGNAL ;
    PORT
      LAYER M5 ;
        RECT  13.824 0 13.848 0.192 ;
    END
  END dr_o[76]
  PIN dr_o[77]
    DIRECTION OUTPUT ;
    USE SIGNAL ;
    PORT
      LAYER M5 ;
        RECT  13.92 0 13.944 0.192 ;
    END
  END dr_o[77]
  PIN dr_o[78]
    DIRECTION OUTPUT ;
    USE SIGNAL ;
    PORT
      LAYER M5 ;
        RECT  14.016 0 14.04 0.192 ;
    END
  END dr_o[78]
  PIN dr_o[79]
    DIRECTION OUTPUT ;
    USE SIGNAL ;
    PORT
      LAYER M5 ;
        RECT  14.112 0 14.136 0.192 ;
    END
  END dr_o[79]
  PIN dr_o[7]
    DIRECTION OUTPUT ;
    USE SIGNAL ;
    PORT
      LAYER M5 ;
        RECT  7.2 0 7.224 0.192 ;
    END
  END dr_o[7]
  PIN dr_o[80]
    DIRECTION OUTPUT ;
    USE SIGNAL ;
    PORT
      LAYER M5 ;
        RECT  14.208 0 14.232 0.192 ;
    END
  END dr_o[80]
  PIN dr_o[81]
    DIRECTION OUTPUT ;
    USE SIGNAL ;
    PORT
      LAYER M5 ;
        RECT  14.304 0 14.328 0.192 ;
    END
  END dr_o[81]
  PIN dr_o[82]
    DIRECTION OUTPUT ;
    USE SIGNAL ;
    PORT
      LAYER M5 ;
        RECT  14.4 0 14.424 0.192 ;
    END
  END dr_o[82]
  PIN dr_o[83]
    DIRECTION OUTPUT ;
    USE SIGNAL ;
    PORT
      LAYER M5 ;
        RECT  14.496 0 14.52 0.192 ;
    END
  END dr_o[83]
  PIN dr_o[84]
    DIRECTION OUTPUT ;
    USE SIGNAL ;
    PORT
      LAYER M5 ;
        RECT  14.592 0 14.616 0.192 ;
    END
  END dr_o[84]
  PIN dr_o[85]
    DIRECTION OUTPUT ;
    USE SIGNAL ;
    PORT
      LAYER M5 ;
        RECT  14.688 0 14.712 0.192 ;
    END
  END dr_o[85]
  PIN dr_o[86]
    DIRECTION OUTPUT ;
    USE SIGNAL ;
    PORT
      LAYER M5 ;
        RECT  14.784 0 14.808 0.192 ;
    END
  END dr_o[86]
  PIN dr_o[87]
    DIRECTION OUTPUT ;
    USE SIGNAL ;
    PORT
      LAYER M5 ;
        RECT  14.88 0 14.904 0.192 ;
    END
  END dr_o[87]
  PIN dr_o[88]
    DIRECTION OUTPUT ;
    USE SIGNAL ;
    PORT
      LAYER M5 ;
        RECT  14.976 0 15 0.192 ;
    END
  END dr_o[88]
  PIN dr_o[89]
    DIRECTION OUTPUT ;
    USE SIGNAL ;
    PORT
      LAYER M5 ;
        RECT  15.072 0 15.096 0.192 ;
    END
  END dr_o[89]
  PIN dr_o[8]
    DIRECTION OUTPUT ;
    USE SIGNAL ;
    PORT
      LAYER M5 ;
        RECT  7.296 0 7.32 0.192 ;
    END
  END dr_o[8]
  PIN dr_o[90]
    DIRECTION OUTPUT ;
    USE SIGNAL ;
    PORT
      LAYER M5 ;
        RECT  15.168 0 15.192 0.192 ;
    END
  END dr_o[90]
  PIN dr_o[91]
    DIRECTION OUTPUT ;
    USE SIGNAL ;
    PORT
      LAYER M5 ;
        RECT  15.264 0 15.288 0.192 ;
    END
  END dr_o[91]
  PIN dr_o[92]
    DIRECTION OUTPUT ;
    USE SIGNAL ;
    PORT
      LAYER M5 ;
        RECT  15.36 0 15.384 0.192 ;
    END
  END dr_o[92]
  PIN dr_o[93]
    DIRECTION OUTPUT ;
    USE SIGNAL ;
    PORT
      LAYER M5 ;
        RECT  15.456 0 15.48 0.192 ;
    END
  END dr_o[93]
  PIN dr_o[94]
    DIRECTION OUTPUT ;
    USE SIGNAL ;
    PORT
      LAYER M5 ;
        RECT  15.552 0 15.576 0.192 ;
    END
  END dr_o[94]
  PIN dr_o[95]
    DIRECTION OUTPUT ;
    USE SIGNAL ;
    PORT
      LAYER M5 ;
        RECT  15.648 0 15.672 0.192 ;
    END
  END dr_o[95]
  PIN dr_o[96]
    DIRECTION OUTPUT ;
    USE SIGNAL ;
    PORT
      LAYER M5 ;
        RECT  15.744 0 15.768 0.192 ;
    END
  END dr_o[96]
  PIN dr_o[97]
    DIRECTION OUTPUT ;
    USE SIGNAL ;
    PORT
      LAYER M5 ;
        RECT  15.84 0 15.864 0.192 ;
    END
  END dr_o[97]
  PIN dr_o[98]
    DIRECTION OUTPUT ;
    USE SIGNAL ;
    PORT
      LAYER M5 ;
        RECT  15.936 0 15.96 0.192 ;
    END
  END dr_o[98]
  PIN dr_o[99]
    DIRECTION OUTPUT ;
    USE SIGNAL ;
    PORT
      LAYER M5 ;
        RECT  16.032 0 16.056 0.192 ;
    END
  END dr_o[99]
  PIN dr_o[9]
    DIRECTION OUTPUT ;
    USE SIGNAL ;
    PORT
      LAYER M5 ;
        RECT  7.392 0 7.416 0.192 ;
    END
  END dr_o[9]
  PIN lane_rst_n
    DIRECTION OUTPUT ;
    USE SIGNAL ;
    PORT
      LAYER M5 ;
        RECT  27.36 0 27.384 0.192 ;
    END
  END lane_rst_n
  PIN rst_n
    DIRECTION INPUT ;
    USE SIGNAL ;
    PORT
      LAYER M4 ;
        RECT  0 21.696 0.192 21.72 ;
    END
  END rst_n
  PIN VDD
    DIRECTION INOUT ;
    USE POWER ;
    PORT
      LAYER M5 ;
        RECT  29.592 2.151 29.712 41.049 ;
        RECT  24.192 2.151 24.312 41.049 ;
        RECT  18.792 2.151 18.912 41.049 ;
        RECT  13.392 2.151 13.512 41.049 ;
        RECT  7.992 2.151 8.112 41.049 ;
        RECT  2.592 2.151 2.712 41.049 ;
    END
  END VDD
  PIN VSS
    DIRECTION INOUT ;
    USE GROUND ;
    PORT
      LAYER M5 ;
        RECT  29.4 2.137 29.52 41.063 ;
        RECT  24 2.137 24.12 41.063 ;
        RECT  18.6 2.137 18.72 41.063 ;
        RECT  13.2 2.137 13.32 41.063 ;
        RECT  7.8 2.137 7.92 41.063 ;
        RECT  2.4 2.137 2.52 41.063 ;
    END
  END VSS
  # OT_OBS_CLOSED layer=M5 d_um=1.536 added=41
  OBS
    LAYER RVTN ;
     RECT  2.16 2.16 30.24 2.295 ;
     RECT  2.16 2.565 30.24 2.835 ;
     RECT  2.16 3.105 30.24 3.375 ;
     RECT  2.16 3.645 30.24 3.915 ;
     RECT  2.16 4.185 30.24 4.455 ;
     RECT  2.16 4.725 30.24 4.995 ;
     RECT  2.16 5.265 30.24 5.535 ;
     RECT  2.16 5.805 30.24 6.075 ;
     RECT  2.16 6.345 30.24 6.615 ;
     RECT  2.16 6.885 30.24 7.155 ;
     RECT  2.16 7.425 30.24 7.695 ;
     RECT  2.16 7.965 30.24 8.235 ;
     RECT  2.16 8.505 30.24 8.775 ;
     RECT  2.16 9.045 30.24 9.315 ;
     RECT  2.16 9.585 30.24 9.855 ;
     RECT  2.16 10.125 30.24 10.395 ;
     RECT  2.16 10.665 30.24 10.935 ;
     RECT  2.16 11.205 30.24 11.475 ;
     RECT  2.16 11.745 30.24 12.015 ;
     RECT  2.16 12.285 30.24 12.555 ;
     RECT  2.16 12.825 30.24 13.095 ;
     RECT  2.16 13.365 30.24 13.635 ;
     RECT  2.16 13.905 30.24 14.175 ;
     RECT  2.16 14.445 30.24 14.715 ;
     RECT  2.16 14.985 30.24 15.255 ;
     RECT  2.16 15.525 30.24 15.795 ;
     RECT  2.16 16.065 30.24 16.335 ;
     RECT  2.16 16.605 30.24 16.875 ;
     RECT  2.16 17.145 30.24 17.415 ;
     RECT  2.16 17.685 30.24 17.955 ;
     RECT  2.16 18.225 30.24 18.495 ;
     RECT  2.16 18.765 30.24 19.035 ;
     RECT  2.16 19.305 30.24 19.575 ;
     RECT  2.16 19.845 30.24 20.115 ;
     RECT  2.16 20.385 30.24 20.655 ;
     RECT  2.16 20.925 30.24 21.195 ;
     RECT  2.16 21.465 30.24 21.735 ;
     RECT  2.16 22.005 30.24 22.275 ;
     RECT  2.16 22.545 30.24 22.815 ;
     RECT  2.16 23.085 30.24 23.355 ;
     RECT  2.16 23.625 30.24 23.895 ;
     RECT  2.16 24.165 30.24 24.435 ;
     RECT  2.16 24.705 30.24 24.975 ;
     RECT  2.16 25.245 30.24 25.515 ;
     RECT  2.16 25.785 30.24 26.055 ;
     RECT  2.16 26.325 30.24 26.595 ;
     RECT  2.16 26.865 30.24 27.135 ;
     RECT  2.16 27.405 30.24 27.675 ;
     RECT  2.16 27.945 30.24 28.215 ;
     RECT  2.16 28.485 30.24 28.755 ;
     RECT  2.16 29.025 30.24 29.295 ;
     RECT  2.16 29.565 30.24 29.835 ;
     RECT  2.16 30.105 30.24 30.375 ;
     RECT  2.16 30.645 30.24 30.915 ;
     RECT  2.16 31.185 30.24 31.455 ;
     RECT  2.16 31.725 30.24 31.995 ;
     RECT  2.16 32.265 30.24 32.535 ;
     RECT  2.16 32.805 30.24 33.075 ;
     RECT  2.16 33.345 30.24 33.615 ;
     RECT  2.16 33.885 30.24 34.155 ;
     RECT  2.16 34.425 30.24 34.695 ;
     RECT  2.16 34.965 30.24 35.235 ;
     RECT  2.16 35.505 30.24 35.775 ;
     RECT  2.16 36.045 30.24 36.315 ;
     RECT  2.16 36.585 30.24 36.855 ;
     RECT  2.16 37.125 30.24 37.395 ;
     RECT  2.16 37.665 30.24 37.935 ;
     RECT  2.16 38.205 30.24 38.475 ;
     RECT  2.16 38.745 30.24 39.015 ;
     RECT  2.16 39.285 30.24 39.555 ;
     RECT  2.16 39.825 30.24 40.095 ;
     RECT  2.16 40.365 30.24 40.635 ;
     RECT  2.16 40.905 30.24 41.04 ;
    LAYER RVTP ;
     RECT  2.16 2.295 30.24 2.565 ;
     RECT  2.16 2.835 30.24 3.105 ;
     RECT  2.16 3.375 30.24 3.645 ;
     RECT  2.16 3.915 30.24 4.185 ;
     RECT  2.16 4.455 30.24 4.725 ;
     RECT  2.16 4.995 30.24 5.265 ;
     RECT  2.16 5.535 30.24 5.805 ;
     RECT  2.16 6.075 30.24 6.345 ;
     RECT  2.16 6.615 30.24 6.885 ;
     RECT  2.16 7.155 30.24 7.425 ;
     RECT  2.16 7.695 30.24 7.965 ;
     RECT  2.16 8.235 30.24 8.505 ;
     RECT  2.16 8.775 30.24 9.045 ;
     RECT  2.16 9.315 30.24 9.585 ;
     RECT  2.16 9.855 30.24 10.125 ;
     RECT  2.16 10.395 30.24 10.665 ;
     RECT  2.16 10.935 30.24 11.205 ;
     RECT  2.16 11.475 30.24 11.745 ;
     RECT  2.16 12.015 30.24 12.285 ;
     RECT  2.16 12.555 30.24 12.825 ;
     RECT  2.16 13.095 30.24 13.365 ;
     RECT  2.16 13.635 30.24 13.905 ;
     RECT  2.16 14.175 30.24 14.445 ;
     RECT  2.16 14.715 30.24 14.985 ;
     RECT  2.16 15.255 30.24 15.525 ;
     RECT  2.16 15.795 30.24 16.065 ;
     RECT  2.16 16.335 30.24 16.605 ;
     RECT  2.16 16.875 30.24 17.145 ;
     RECT  2.16 17.415 30.24 17.685 ;
     RECT  2.16 17.955 30.24 18.225 ;
     RECT  2.16 18.495 30.24 18.765 ;
     RECT  2.16 19.035 30.24 19.305 ;
     RECT  2.16 19.575 30.24 19.845 ;
     RECT  2.16 20.115 30.24 20.385 ;
     RECT  2.16 20.655 30.24 20.925 ;
     RECT  2.16 21.195 30.24 21.465 ;
     RECT  2.16 21.735 30.24 22.005 ;
     RECT  2.16 22.275 30.24 22.545 ;
     RECT  2.16 22.815 30.24 23.085 ;
     RECT  2.16 23.355 30.24 23.625 ;
     RECT  2.16 23.895 30.24 24.165 ;
     RECT  2.16 24.435 30.24 24.705 ;
     RECT  2.16 24.975 30.24 25.245 ;
     RECT  2.16 25.515 30.24 25.785 ;
     RECT  2.16 26.055 30.24 26.325 ;
     RECT  2.16 26.595 30.24 26.865 ;
     RECT  2.16 27.135 30.24 27.405 ;
     RECT  2.16 27.675 30.24 27.945 ;
     RECT  2.16 28.215 30.24 28.485 ;
     RECT  2.16 28.755 30.24 29.025 ;
     RECT  2.16 29.295 30.24 29.565 ;
     RECT  2.16 29.835 30.24 30.105 ;
     RECT  2.16 30.375 30.24 30.645 ;
     RECT  2.16 30.915 30.24 31.185 ;
     RECT  2.16 31.455 30.24 31.725 ;
     RECT  2.16 31.995 30.24 32.265 ;
     RECT  2.16 32.535 30.24 32.805 ;
     RECT  2.16 33.075 30.24 33.345 ;
     RECT  2.16 33.615 30.24 33.885 ;
     RECT  2.16 34.155 30.24 34.425 ;
     RECT  2.16 34.695 30.24 34.965 ;
     RECT  2.16 35.235 30.24 35.505 ;
     RECT  2.16 35.775 30.24 36.045 ;
     RECT  2.16 36.315 30.24 36.585 ;
     RECT  2.16 36.855 30.24 37.125 ;
     RECT  2.16 37.395 30.24 37.665 ;
     RECT  2.16 37.935 30.24 38.205 ;
     RECT  2.16 38.475 30.24 38.745 ;
     RECT  2.16 39.015 30.24 39.285 ;
     RECT  2.16 39.555 30.24 39.825 ;
     RECT  2.16 40.095 30.24 40.365 ;
     RECT  2.16 40.635 30.24 40.905 ;
    LAYER M1 ;
     RECT  2.16 2.151 30.24 41.049 ;
    LAYER M2 ;
     RECT  2.16 2.151 5.179 41.049 ;
     RECT  5.179 2.106 6.071 41.049 ;
     RECT  6.071 2.151 8.023 41.049 ;
     RECT  8.023 2.106 8.483 41.049 ;
     RECT  8.483 2.151 19.147 41.049 ;
     RECT  19.147 2.106 19.607 41.049 ;
     RECT  19.607 2.151 26.167 41.049 ;
     RECT  26.167 2.106 27.383 41.049 ;
     RECT  27.383 2.151 30.24 41.049 ;
     RECT  30.24 8.82 30.659 34.686 ;
     RECT  30.659 8.82 30.767 34.182 ;
     RECT  30.767 8.82 30.803 30.366 ;
     RECT  30.803 8.82 30.839 13.356 ;
     RECT  30.803 14.526 30.839 14.814 ;
     RECT  30.803 15.57 30.839 16.866 ;
     RECT  30.803 17.658 30.839 19.566 ;
     RECT  30.803 20.358 30.839 22.806 ;
     RECT  30.803 23.634 30.839 26.316 ;
     RECT  30.767 31.23 30.839 34.182 ;
     RECT  30.839 9.63 30.875 12.852 ;
     RECT  30.839 15.57 30.875 16.668 ;
     RECT  30.839 20.358 30.875 22.644 ;
     RECT  30.803 27.108 30.875 30.366 ;
     RECT  30.875 9.63 30.911 12.114 ;
     RECT  30.839 18.666 30.911 19.368 ;
     RECT  30.875 27.918 30.911 30.366 ;
     RECT  30.839 31.932 30.911 34.182 ;
     RECT  30.911 9.63 30.947 10.386 ;
     RECT  30.875 20.358 30.947 21.726 ;
     RECT  30.947 20.358 30.983 21.384 ;
     RECT  30.839 14.526 31.055 14.544 ;
     RECT  30.947 9.63 31.379 10.188 ;
     RECT  30.911 11.448 31.379 12.114 ;
     RECT  30.875 15.57 31.379 16.596 ;
     RECT  30.911 19.278 31.379 19.368 ;
     RECT  30.839 24.21 31.379 25.038 ;
     RECT  30.839 26.298 31.379 26.316 ;
     RECT  30.911 28.566 31.379 30.366 ;
     RECT  30.911 31.932 31.379 33.984 ;
     RECT  30.839 8.82 31.415 8.838 ;
     RECT  30.839 17.658 31.415 17.676 ;
     RECT  31.379 19.278 31.415 19.296 ;
     RECT  30.983 20.358 31.415 20.988 ;
     RECT  31.379 24.48 31.415 24.498 ;
     RECT  30.875 27.108 31.415 27.126 ;
     RECT  31.379 28.566 31.415 30.096 ;
     RECT  31.379 32.472 31.415 32.796 ;
     RECT  31.379 33.966 31.415 33.984 ;
     RECT  31.379 9.63 31.451 9.648 ;
     RECT  31.379 11.448 31.451 11.466 ;
     RECT  31.415 32.778 31.451 32.796 ;
     RECT  31.415 28.836 31.523 29.322 ;
     RECT  31.523 29.304 32.171 29.322 ;
     RECT  32.179 23.598 32.279 23.616 ;
    LAYER M3 ;
     RECT  4.86 0.187 5.886 0.235 ;
     RECT  10.044 0.187 10.062 0.235 ;
     RECT  10.908 0.187 12.114 0.235 ;
     RECT  12.888 0.187 12.906 0.235 ;
     RECT  13.788 0.187 13.95 0.235 ;
     RECT  17.856 0.187 19.998 0.317 ;
     RECT  20.736 0.187 20.754 0.317 ;
     RECT  15.3 0.187 15.318 0.523 ;
     RECT  16.344 0.187 16.614 0.523 ;
     RECT  4.752 0.235 5.886 0.571 ;
     RECT  8.136 0.187 8.334 0.571 ;
     RECT  9.108 0.187 9.126 0.571 ;
     RECT  9.864 0.235 10.062 0.571 ;
     RECT  10.908 0.235 12.906 0.571 ;
     RECT  13.788 0.235 14.058 0.571 ;
     RECT  15.3 0.523 16.614 0.571 ;
     RECT  26.064 0.475 26.082 0.571 ;
     RECT  26.028 0.571 26.082 0.619 ;
     RECT  17.856 0.317 19.278 1.051 ;
     RECT  8.136 0.571 12.906 1.099 ;
     RECT  22.752 0.187 22.77 1.099 ;
     RECT  4.752 0.571 6.534 1.147 ;
     RECT  7.632 1.099 12.906 1.147 ;
     RECT  13.788 0.571 16.614 1.147 ;
     RECT  22.752 1.099 23.454 1.147 ;
     RECT  17.856 1.051 19.53 1.627 ;
     RECT  4.752 1.147 16.902 1.723 ;
     RECT  17.856 1.627 19.782 1.723 ;
     RECT  20.736 1.147 20.754 1.723 ;
     RECT  22.716 1.147 23.454 1.723 ;
     RECT  24.444 0.187 24.858 1.723 ;
     RECT  26.028 0.619 26.226 1.723 ;
     RECT  26.964 0.523 26.982 1.723 ;
     RECT  24.444 1.723 27.342 1.867 ;
     RECT  4.752 1.723 23.67 2.011 ;
     RECT  24.444 1.867 27.45 2.011 ;
     RECT  4.752 2.011 27.45 2.191 ;
     RECT  28.188 1.771 28.206 2.191 ;
     RECT  4.716 2.191 28.206 2.371 ;
     RECT  29.415 2.143 29.505 2.371 ;
     RECT  2.415 2.143 2.505 2.413 ;
     RECT  4.716 2.371 29.505 2.413 ;
     RECT  4.716 2.413 29.697 2.497 ;
     RECT  4.572 2.497 29.697 2.605 ;
     RECT  4.536 2.605 29.697 2.641 ;
     RECT  4.5 2.641 29.697 2.911 ;
     RECT  4.248 2.911 29.697 3.685 ;
     RECT  4.068 3.685 29.697 4.379 ;
     RECT  4.068 4.379 28.098 4.757 ;
     RECT  4.464 4.757 28.098 5.189 ;
     RECT  4.572 5.189 28.098 5.459 ;
     RECT  4.572 5.459 28.026 5.693 ;
     RECT  4.572 5.693 27.882 6.107 ;
     RECT  4.86 6.107 27.882 6.269 ;
     RECT  4.968 6.269 27.882 6.539 ;
     RECT  5.148 6.539 27.882 7.385 ;
     RECT  5.22 7.385 27.882 7.435 ;
     RECT  28.836 4.379 29.697 7.435 ;
     RECT  5.22 7.435 29.697 8.251 ;
     RECT  5.004 8.251 29.697 8.303 ;
     RECT  5.724 8.303 29.697 8.311 ;
     RECT  5.724 8.311 29.934 8.429 ;
     RECT  5.724 8.429 29.826 8.969 ;
     RECT  31.392 8.815 31.41 9.085 ;
     RECT  5.868 8.969 29.826 9.319 ;
     RECT  30.816 9.085 31.41 9.355 ;
     RECT  5.868 9.319 29.898 9.419 ;
     RECT  6.156 9.419 29.898 9.545 ;
     RECT  30.78 9.355 31.41 9.625 ;
     RECT  6.336 9.545 29.898 9.661 ;
     RECT  6.336 9.661 30.042 9.787 ;
     RECT  30.78 9.625 31.446 9.787 ;
     RECT  6.336 9.787 31.446 11.471 ;
     RECT  6.336 11.471 31.41 11.669 ;
     RECT  6.732 11.669 31.41 11.933 ;
     RECT  6.732 11.933 31.374 11.939 ;
     RECT  7.02 11.939 31.374 12.515 ;
     RECT  7.164 12.515 31.374 12.797 ;
     RECT  7.164 12.797 30.906 13.277 ;
     RECT  7.164 13.277 30.87 13.373 ;
     RECT  7.164 13.373 30.834 13.397 ;
     RECT  10.332 13.397 30.834 13.565 ;
     RECT  7.164 13.397 9.378 13.631 ;
     RECT  7.164 13.631 8.37 13.667 ;
     RECT  7.815 13.667 8.37 13.829 ;
     RECT  10.332 13.565 30.798 14.135 ;
     RECT  9.324 13.631 9.378 14.243 ;
     RECT  9.324 14.243 9.342 14.279 ;
     RECT  10.332 14.135 11.934 14.369 ;
     RECT  10.872 14.369 11.934 14.441 ;
     RECT  12.816 14.135 30.798 14.521 ;
     RECT  11.088 14.441 11.934 14.639 ;
     RECT  11.52 14.639 11.934 14.909 ;
     RECT  11.628 14.909 11.934 15.061 ;
     RECT  11.628 15.061 11.97 15.359 ;
     RECT  12.816 14.521 31.05 15.547 ;
     RECT  11.844 15.359 11.97 15.719 ;
     RECT  12.816 15.547 31.374 15.989 ;
     RECT  11.952 15.719 11.97 16.061 ;
     RECT  12.924 15.989 31.374 16.799 ;
     RECT  13.032 16.799 31.374 17.609 ;
     RECT  13.14 17.609 31.374 17.653 ;
     RECT  13.14 17.653 31.41 17.879 ;
     RECT  14.256 17.879 31.41 17.885 ;
     RECT  13.14 17.879 13.497 18.149 ;
     RECT  14.256 17.885 31.374 18.149 ;
     RECT  10.044 18.301 10.062 18.419 ;
     RECT  14.328 18.149 31.374 18.989 ;
     RECT  13.215 18.149 13.497 19.111 ;
     RECT  14.328 18.989 14.526 19.111 ;
     RECT  13.215 19.111 14.526 19.229 ;
     RECT  15.444 18.989 31.374 19.273 ;
     RECT  13.215 19.229 13.878 19.373 ;
     RECT  15.444 19.273 31.41 19.499 ;
     RECT  9.396 18.535 9.414 20.039 ;
     RECT  16.02 19.499 31.41 20.345 ;
     RECT  16.02 20.345 16.038 20.489 ;
     RECT  16.884 20.345 31.41 20.849 ;
     RECT  16.92 20.849 31.41 20.993 ;
     RECT  16.92 20.993 30.978 21.389 ;
     RECT  16.92 21.389 30.942 21.659 ;
     RECT  4.536 20.155 4.554 21.725 ;
     RECT  17.568 21.659 30.942 21.731 ;
     RECT  17.568 21.731 30.87 22.001 ;
     RECT  17.856 22.001 30.87 22.199 ;
     RECT  18.54 22.199 30.87 22.469 ;
     RECT  18.615 22.469 30.87 23.549 ;
     RECT  32.256 23.563 32.274 23.593 ;
     RECT  32.184 23.593 32.274 23.621 ;
     RECT  32.184 23.621 32.202 23.645 ;
     RECT  19.764 23.549 30.87 23.729 ;
     RECT  20.448 23.729 30.87 23.819 ;
     RECT  20.52 23.819 30.87 23.899 ;
     RECT  20.52 23.899 31.374 24.089 ;
     RECT  20.628 24.089 31.374 24.359 ;
     RECT  20.664 24.359 31.374 24.475 ;
     RECT  20.664 24.475 31.41 24.605 ;
     RECT  20.664 24.605 31.374 24.899 ;
     RECT  20.808 24.899 31.374 25.043 ;
     RECT  20.808 25.043 30.834 25.169 ;
     RECT  21.312 25.169 30.834 25.511 ;
     RECT  21.564 25.511 30.834 25.547 ;
     RECT  21.744 25.547 30.834 26.293 ;
     RECT  21.744 26.293 31.374 27.103 ;
     RECT  21.744 27.103 31.41 27.239 ;
     RECT  22.86 27.239 31.41 28.123 ;
     RECT  32.148 26.587 32.166 28.123 ;
     RECT  22.86 28.123 32.166 28.589 ;
     RECT  23.58 28.589 32.166 28.859 ;
     RECT  23.832 28.859 32.166 29.291 ;
     RECT  32.148 29.291 32.166 29.327 ;
     RECT  23.832 29.291 31.41 29.605 ;
     RECT  23.688 29.605 31.41 29.645 ;
     RECT  21.744 27.239 21.762 29.669 ;
     RECT  22.824 29.641 22.842 29.939 ;
     RECT  23.832 29.645 31.41 30.749 ;
     RECT  23.976 30.749 31.41 30.875 ;
     RECT  24.015 30.875 31.41 31.325 ;
     RECT  24.015 31.325 31.374 32.443 ;
     RECT  24.015 32.443 31.41 32.731 ;
     RECT  24.015 32.731 31.446 32.801 ;
     RECT  24.015 32.801 31.41 33.005 ;
     RECT  25.056 33.005 31.41 33.269 ;
     RECT  25.164 33.269 31.41 33.377 ;
     RECT  25.164 33.377 25.47 33.449 ;
     RECT  26.244 33.377 31.41 33.449 ;
     RECT  25.38 33.449 25.47 33.809 ;
     RECT  26.28 33.449 31.41 33.989 ;
     RECT  26.28 33.989 30.906 34.187 ;
     RECT  25.416 33.809 25.47 34.501 ;
     RECT  26.28 34.187 30.654 34.501 ;
     RECT  25.416 34.501 30.654 34.619 ;
     RECT  25.56 34.619 30.654 34.691 ;
     RECT  25.56 34.691 30.114 34.925 ;
     RECT  25.56 34.925 25.578 34.973 ;
     RECT  26.316 34.925 30.114 35.069 ;
     RECT  26.64 35.069 29.697 35.159 ;
     RECT  26.712 35.159 29.697 35.195 ;
     RECT  27.648 35.195 29.697 35.429 ;
     RECT  26.712 35.195 26.73 35.465 ;
     RECT  27.72 35.429 29.697 35.465 ;
     RECT  28.152 35.465 29.697 35.573 ;
     RECT  28.152 35.573 28.17 35.609 ;
     RECT  2.415 2.413 2.697 40.787 ;
     RECT  7.815 13.829 8.097 40.787 ;
     RECT  13.215 19.373 13.497 40.787 ;
     RECT  18.615 23.549 18.897 40.787 ;
     RECT  24.015 33.005 24.297 40.787 ;
     RECT  29.415 35.573 29.697 40.787 ;
     RECT  2.415 40.787 2.505 41.057 ;
     RECT  7.815 40.787 7.905 41.057 ;
     RECT  13.215 40.787 13.305 41.057 ;
     RECT  18.615 40.787 18.705 41.057 ;
     RECT  24.015 40.787 24.105 41.057 ;
     RECT  29.415 40.787 29.505 41.057 ;
    LAYER M4 ;
     RECT  0.156 21.6 0.227 21.72 ;
     RECT  0.181 19.824 2.408 19.848 ;
     RECT  0.227 21.696 2.408 21.72 ;
     RECT  2.408 2.148 2.512 41.052 ;
     RECT  2.512 2.418 2.704 40.782 ;
     RECT  2.704 21.696 4.565 21.72 ;
     RECT  4.741 0.24 4.849 0.264 ;
     RECT  4.849 6.24 4.885 6.264 ;
     RECT  4.849 0.192 4.949 0.264 ;
     RECT  4.993 8.256 5.173 8.28 ;
     RECT  4.949 0.192 5.411 1.176 ;
     RECT  4.885 6.144 5.641 6.264 ;
     RECT  5.137 2.256 5.749 2.28 ;
     RECT  5.641 6.144 5.893 6.552 ;
     RECT  5.411 0.192 5.897 0.6 ;
     RECT  5.893 5.232 5.941 6.552 ;
     RECT  5.941 5.136 6.037 6.552 ;
     RECT  5.173 7.728 6.037 8.28 ;
     RECT  6.037 5.136 6.113 8.28 ;
     RECT  6.113 5.232 6.181 8.28 ;
     RECT  5.749 1.728 6.275 2.28 ;
     RECT  6.181 5.232 6.365 9.096 ;
     RECT  5.461 3.984 6.524 4.008 ;
     RECT  5.897 0.576 6.545 0.6 ;
     RECT  6.397 10.176 6.565 10.2 ;
     RECT  6.365 5.856 6.649 9.096 ;
     RECT  6.524 3.408 6.659 4.008 ;
     RECT  6.649 5.856 6.685 9.192 ;
     RECT  6.565 10.176 6.685 10.872 ;
     RECT  6.659 3.408 6.805 3.912 ;
     RECT  6.275 1.728 7.093 1.896 ;
     RECT  6.685 5.856 7.153 10.872 ;
     RECT  7.093 1.152 7.261 1.896 ;
     RECT  6.805 2.88 7.261 3.912 ;
     RECT  7.153 5.856 7.477 11.256 ;
     RECT  7.261 1.152 7.621 3.912 ;
     RECT  7.621 1.104 7.808 3.912 ;
     RECT  7.477 5.136 7.808 11.256 ;
     RECT  7.369 12.528 7.808 12.552 ;
     RECT  2.704 19.824 7.808 19.848 ;
     RECT  7.808 1.104 7.907 41.052 ;
     RECT  7.907 1.728 7.912 41.052 ;
     RECT  7.957 0.288 8.053 0.648 ;
     RECT  7.912 1.728 8.104 40.782 ;
     RECT  8.104 5.136 8.489 9.816 ;
     RECT  8.104 12.528 8.785 13.128 ;
     RECT  8.053 0.192 8.884 0.648 ;
     RECT  8.489 5.136 8.885 8.04 ;
     RECT  8.104 2.736 9.109 4.008 ;
     RECT  8.885 5.136 9.109 6.12 ;
     RECT  9.109 2.736 9.137 6.12 ;
     RECT  8.104 11.088 9.169 11.4 ;
     RECT  8.104 1.728 9.269 1.752 ;
     RECT  9.137 2.736 9.269 6.072 ;
     RECT  8.489 9.072 9.313 9.816 ;
     RECT  9.269 1.728 9.533 6.072 ;
     RECT  9.169 11.088 9.548 11.448 ;
     RECT  8.785 12.528 9.548 12.792 ;
     RECT  9.533 5.136 9.605 6.072 ;
     RECT  9.548 11.088 9.635 12.792 ;
     RECT  9.533 1.728 9.721 4.008 ;
     RECT  9.721 3.888 9.731 4.008 ;
     RECT  9.605 5.136 9.749 5.88 ;
     RECT  8.885 7.2 9.817 8.04 ;
     RECT  9.313 9.072 9.817 9.864 ;
     RECT  8.884 0.192 9.925 0.696 ;
     RECT  9.721 1.728 9.925 2.904 ;
     RECT  9.817 7.2 9.961 9.864 ;
     RECT  9.635 11.088 9.961 11.448 ;
     RECT  9.925 0.192 10.019 2.904 ;
     RECT  9.749 5.136 10.037 5.736 ;
     RECT  10.019 1.728 10.145 2.904 ;
     RECT  10.037 5.136 10.181 5.208 ;
     RECT  9.961 7.2 10.321 11.448 ;
     RECT  9.635 12.768 10.321 12.792 ;
     RECT  10.145 2.88 10.397 2.904 ;
     RECT  10.321 12.768 10.501 12.888 ;
     RECT  9.731 3.984 10.541 4.008 ;
     RECT  10.181 5.136 10.541 5.16 ;
     RECT  10.321 7.104 10.609 11.448 ;
     RECT  10.501 12.768 10.681 12.936 ;
     RECT  10.609 7.104 10.861 11.496 ;
     RECT  10.897 4.992 11.045 5.112 ;
     RECT  11.045 4.992 11.153 5.016 ;
     RECT  10.825 3.936 11.257 3.96 ;
     RECT  10.681 12.768 11.545 13.656 ;
     RECT  11.257 3.648 11.549 3.96 ;
     RECT  10.861 7.104 11.549 11.544 ;
     RECT  10.145 1.728 11.605 1.896 ;
     RECT  11.605 1.728 11.692 2.328 ;
     RECT  11.701 3.408 11.725 3.432 ;
     RECT  11.692 1.728 11.939 1.8 ;
     RECT  10.019 0.192 12.049 0.6 ;
     RECT  11.939 1.728 12.049 1.752 ;
     RECT  11.549 10.608 12.049 11.544 ;
     RECT  11.545 12.768 12.049 14.232 ;
     RECT  11.581 4.464 12.121 4.728 ;
     RECT  12.049 0.192 12.227 1.752 ;
     RECT  11.725 3.312 12.265 3.432 ;
     RECT  12.121 4.464 12.301 5.64 ;
     RECT  11.549 7.104 12.445 9.096 ;
     RECT  12.049 10.608 12.553 14.232 ;
     RECT  12.301 4.464 12.589 5.736 ;
     RECT  12.445 6.816 12.589 9.096 ;
     RECT  12.265 2.88 12.877 3.432 ;
     RECT  12.589 4.464 12.877 9.096 ;
     RECT  12.227 1.728 13.013 1.752 ;
     RECT  12.877 2.88 13.093 9.096 ;
     RECT  13.013 1.728 13.208 1.8 ;
     RECT  13.093 2.88 13.208 9.336 ;
     RECT  12.553 10.32 13.208 14.232 ;
     RECT  11.905 15.264 13.208 15.288 ;
     RECT  8.104 19.824 13.208 19.848 ;
     RECT  13.208 1.728 13.312 41.052 ;
     RECT  12.227 0.192 13.429 0.312 ;
     RECT  13.312 1.728 13.429 40.782 ;
     RECT  13.429 0.192 13.504 40.782 ;
     RECT  13.504 5.184 13.619 5.208 ;
     RECT  13.504 0.192 13.673 4.056 ;
     RECT  13.673 0.192 13.853 2.856 ;
     RECT  13.853 0.192 13.996 0.648 ;
     RECT  13.996 0.24 14.069 0.648 ;
     RECT  13.504 17.136 14.435 17.16 ;
     RECT  13.504 6.288 14.485 13.704 ;
     RECT  14.485 5.952 14.605 13.704 ;
     RECT  14.605 5.952 14.677 13.944 ;
     RECT  13.504 15.264 14.677 15.288 ;
     RECT  13.504 18.912 14.677 19.848 ;
     RECT  13.853 1.728 14.681 2.856 ;
     RECT  14.069 0.576 14.789 0.648 ;
     RECT  13.673 4.032 14.821 4.056 ;
     RECT  14.677 18.192 14.821 19.848 ;
     RECT  14.821 3.936 14.824 4.056 ;
     RECT  14.677 5.952 14.825 15.288 ;
     RECT  14.824 3.936 14.929 4.104 ;
     RECT  14.825 5.952 14.965 13.08 ;
     RECT  14.821 18.096 15.005 19.848 ;
     RECT  14.965 5.712 15.037 13.08 ;
     RECT  15.037 5.088 15.077 13.08 ;
     RECT  15.077 6.336 15.149 13.08 ;
     RECT  14.929 3.408 15.185 4.104 ;
     RECT  15.149 6.336 15.257 11.88 ;
     RECT  15.077 5.088 15.401 5.16 ;
     RECT  15.257 6.384 15.401 11.88 ;
     RECT  15.005 18.576 15.761 19.848 ;
     RECT  14.825 14.592 15.905 15.192 ;
     RECT  14.681 1.728 15.941 2.376 ;
     RECT  15.245 0.192 15.98 0.216 ;
     RECT  15.401 6.576 16.117 11.88 ;
     RECT  15.149 13.008 16.333 13.08 ;
     RECT  16.333 13.008 16.369 13.176 ;
     RECT  15.401 5.136 16.405 5.16 ;
     RECT  15.905 14.88 16.409 15.192 ;
     RECT  15.185 3.408 16.453 3.432 ;
     RECT  16.453 3.36 16.477 3.432 ;
     RECT  16.405 4.512 16.477 5.16 ;
     RECT  16.477 3.36 16.561 5.16 ;
     RECT  16.561 4.512 16.589 5.16 ;
     RECT  16.117 6.576 16.589 12.024 ;
     RECT  16.369 13.008 16.589 13.896 ;
     RECT  15.98 0.192 16.669 0.552 ;
     RECT  16.589 4.56 16.697 5.16 ;
     RECT  16.589 10.56 16.801 12.024 ;
     RECT  16.589 13.008 16.801 13.032 ;
     RECT  15.941 1.728 16.873 2.328 ;
     RECT  16.873 1.152 16.957 2.328 ;
     RECT  16.697 5.04 16.973 5.16 ;
     RECT  16.589 6.576 16.973 9.096 ;
     RECT  16.973 5.04 17.057 9.096 ;
     RECT  16.561 3.36 17.197 3.432 ;
     RECT  17.057 5.04 17.219 5.256 ;
     RECT  16.957 1.728 17.365 2.328 ;
     RECT  17.197 3.312 17.365 3.432 ;
     RECT  17.233 14.112 17.557 14.136 ;
     RECT  16.409 15.12 17.557 15.192 ;
     RECT  16.801 10.56 17.593 13.032 ;
     RECT  15.761 18.96 17.701 19.848 ;
     RECT  17.365 1.728 17.773 3.432 ;
     RECT  17.593 10.128 17.917 13.032 ;
     RECT  17.557 14.112 17.917 15.192 ;
     RECT  17.653 0.192 17.941 0.264 ;
     RECT  13.504 21.12 18.037 21.144 ;
     RECT  17.917 10.128 18.181 15.192 ;
     RECT  17.701 16.32 18.181 16.344 ;
     RECT  18.181 10.128 18.313 16.344 ;
     RECT  17.701 18.96 18.313 19.944 ;
     RECT  17.773 1.728 18.325 4.2 ;
     RECT  17.941 0.192 18.529 0.6 ;
     RECT  18.325 1.728 18.529 4.728 ;
     RECT  18.529 0.192 18.608 4.728 ;
     RECT  17.057 6.288 18.608 9.096 ;
     RECT  18.313 10.128 18.608 16.392 ;
     RECT  18.313 18.48 18.608 19.944 ;
     RECT  18.037 21.12 18.608 21.768 ;
     RECT  18.608 0.192 18.712 41.052 ;
     RECT  18.712 0.192 18.904 40.782 ;
     RECT  18.904 2.832 19.073 16.152 ;
     RECT  19.073 2.832 19.091 5.832 ;
     RECT  19.091 3.84 19.139 5.832 ;
     RECT  18.904 17.76 19.181 18.984 ;
     RECT  18.904 0.192 19.369 1.848 ;
     RECT  19.369 0.192 19.619 1.8 ;
     RECT  19.073 6.816 19.969 16.152 ;
     RECT  19.091 2.832 20.053 2.856 ;
     RECT  19.139 3.84 20.053 5.16 ;
     RECT  19.969 6.816 20.185 16.632 ;
     RECT  20.053 2.832 20.333 5.16 ;
     RECT  20.333 4.56 20.341 5.16 ;
     RECT  20.333 2.832 20.428 3.432 ;
     RECT  20.185 6.816 20.437 17.16 ;
     RECT  19.181 18.24 20.437 18.984 ;
     RECT  20.341 4.56 20.441 5.688 ;
     RECT  19.619 1.632 20.501 1.8 ;
     RECT  20.428 2.832 20.501 2.856 ;
     RECT  20.441 4.56 20.521 5.16 ;
     RECT  20.437 6.816 20.531 18.984 ;
     RECT  19.619 0.192 20.629 0.312 ;
     RECT  20.501 1.632 20.629 2.856 ;
     RECT  20.629 0.192 20.765 2.856 ;
     RECT  20.765 1.728 20.771 2.856 ;
     RECT  20.684 23.904 20.771 23.928 ;
     RECT  20.765 0.192 20.809 0.216 ;
     RECT  20.521 4.56 20.909 4.584 ;
     RECT  18.904 21.12 21.085 21.768 ;
     RECT  21.337 4.176 21.485 4.2 ;
     RECT  21.085 21.12 21.625 21.864 ;
     RECT  21.625 20.88 21.661 21.864 ;
     RECT  21.493 5.712 21.836 5.736 ;
     RECT  21.661 20.784 21.841 21.864 ;
     RECT  20.771 1.728 21.877 2.568 ;
     RECT  21.781 3.984 21.877 4.008 ;
     RECT  21.877 1.728 21.881 4.008 ;
     RECT  21.841 20.784 21.913 22.104 ;
     RECT  20.725 25.104 21.949 25.128 ;
     RECT  21.949 25.056 21.985 25.128 ;
     RECT  21.913 20.592 22.021 22.104 ;
     RECT  20.531 6.816 22.057 16.92 ;
     RECT  20.531 18.432 22.057 18.984 ;
     RECT  22.021 20.592 22.093 23.016 ;
     RECT  21.985 24.816 22.165 25.128 ;
     RECT  21.881 1.728 22.205 3.96 ;
     RECT  22.165 24.48 22.345 25.128 ;
     RECT  22.165 26.208 22.345 26.232 ;
     RECT  21.836 5.616 22.381 5.736 ;
     RECT  22.093 20.16 22.417 23.016 ;
     RECT  22.345 24.48 22.417 26.232 ;
     RECT  22.205 1.728 22.645 2.856 ;
     RECT  22.645 1.152 22.7 2.856 ;
     RECT  22.7 0.192 22.787 2.856 ;
     RECT  22.205 3.84 22.787 3.96 ;
     RECT  22.381 5.088 22.817 5.736 ;
     RECT  22.817 5.712 22.931 5.736 ;
     RECT  22.057 6.816 22.961 18.984 ;
     RECT  22.961 8.448 23.029 18.984 ;
     RECT  22.417 20.16 23.029 26.232 ;
     RECT  23.029 8.448 23.065 26.232 ;
     RECT  22.961 6.816 23.137 7.464 ;
     RECT  22.787 1.104 23.173 2.856 ;
     RECT  23.065 8.448 23.317 26.568 ;
     RECT  23.317 8.448 23.461 26.712 ;
     RECT  23.084 27.792 23.461 27.816 ;
     RECT  23.461 8.448 23.497 27.816 ;
     RECT  23.173 1.104 23.555 2.904 ;
     RECT  23.125 29.76 23.677 29.784 ;
     RECT  23.555 1.728 23.797 2.904 ;
     RECT  22.921 3.984 23.797 4.584 ;
     RECT  23.677 29.616 23.857 29.784 ;
     RECT  23.797 1.728 23.893 4.584 ;
     RECT  23.893 1.728 24.008 5.208 ;
     RECT  23.137 6.288 24.008 7.464 ;
     RECT  23.497 8.448 24.008 27.864 ;
     RECT  23.857 28.944 24.008 29.784 ;
     RECT  24.008 1.728 24.112 41.052 ;
     RECT  24.112 1.728 24.304 40.782 ;
     RECT  24.085 0.288 24.373 0.504 ;
     RECT  24.373 0.192 24.515 0.504 ;
     RECT  24.304 1.728 24.515 30.408 ;
     RECT  24.515 0.192 24.553 0.312 ;
     RECT  24.553 0.192 24.869 0.216 ;
     RECT  24.515 1.728 24.869 5.16 ;
     RECT  24.869 5.136 24.905 5.16 ;
     RECT  24.869 1.728 24.947 3.96 ;
     RECT  24.515 6.24 25.273 30.408 ;
     RECT  25.273 6.816 25.369 30.408 ;
     RECT  24.304 31.392 25.369 33.672 ;
     RECT  25.369 6.816 25.379 33.672 ;
     RECT  25.379 7.44 25.441 33.672 ;
     RECT  25.441 7.44 25.769 33.72 ;
     RECT  25.769 7.872 25.909 33.72 ;
     RECT  25.549 34.944 25.909 34.968 ;
     RECT  25.813 0.576 26.053 0.6 ;
     RECT  26.053 0.48 26.101 0.6 ;
     RECT  24.947 1.728 26.165 3.432 ;
     RECT  26.005 4.56 26.197 4.584 ;
     RECT  26.101 0.48 26.237 0.648 ;
     RECT  26.197 4.56 26.245 4.632 ;
     RECT  26.165 2.88 26.291 3.432 ;
     RECT  26.237 0.48 26.339 0.552 ;
     RECT  26.291 2.88 26.381 2.904 ;
     RECT  25.909 7.872 26.389 34.968 ;
     RECT  26.245 4.56 26.525 5.544 ;
     RECT  26.389 7.872 26.581 35.016 ;
     RECT  26.525 4.56 26.633 5.16 ;
     RECT  26.581 7.872 26.657 35.16 ;
     RECT  26.633 4.56 26.705 4.584 ;
     RECT  26.339 0.528 27.011 0.552 ;
     RECT  26.165 1.728 27.233 1.8 ;
     RECT  27.233 1.728 27.316 1.848 ;
     RECT  27.316 1.728 27.353 1.896 ;
     RECT  27.353 1.776 27.461 1.896 ;
     RECT  26.657 7.872 27.5 35.352 ;
     RECT  27.596 6.24 27.683 6.264 ;
     RECT  27.5 7.776 27.685 35.352 ;
     RECT  27.685 7.776 28.021 35.448 ;
     RECT  27.997 5.664 28.081 5.688 ;
     RECT  28.021 7.44 28.145 35.448 ;
     RECT  27.461 1.776 28.217 1.8 ;
     RECT  28.429 2.832 29.408 2.856 ;
     RECT  28.145 7.44 29.408 35.16 ;
     RECT  29.408 2.148 29.512 41.052 ;
     RECT  29.512 2.418 29.704 40.782 ;
     RECT  29.704 9.792 30.125 32.664 ;
     RECT  30.125 10.464 31.417 32.664 ;
     RECT  31.417 10.464 32.22 32.76 ;
     RECT  32.22 23.568 32.285 23.592 ;
    LAYER M5 ;
     RECT  4.992 0.144 27.384 1.187 ;
     RECT  5.472 1.187 27.384 1.907 ;
     RECT  2.4 2.137 2.52 2.151 ;
     RECT  29.4 2.137 29.52 2.151 ;
     RECT  11.616 1.907 26.616 2.387 ;
     RECT  29.4 2.151 29.712 2.821 ;
     RECT  16.416 2.387 26.616 2.915 ;
     RECT  16.416 2.915 24.984 3.397 ;
     RECT  5.472 1.907 10.488 3.925 ;
     RECT  11.616 2.387 15 3.925 ;
     RECT  5.472 3.925 15 4.019 ;
     RECT  26.016 2.915 26.616 4.595 ;
     RECT  26.208 4.595 26.616 4.643 ;
     RECT  5.952 4.019 15 4.739 ;
     RECT  5.952 4.739 10.968 5.171 ;
     RECT  26.256 4.643 26.616 5.171 ;
     RECT  6.576 5.171 9.96 5.219 ;
     RECT  26.256 5.171 26.28 5.555 ;
     RECT  28.464 2.821 29.712 5.653 ;
     RECT  12.24 4.739 15 5.747 ;
     RECT  16.128 3.397 24.984 5.747 ;
     RECT  6.576 5.219 9.672 5.891 ;
     RECT  7.8 5.891 9.048 6.131 ;
     RECT  21.888 5.747 24.984 6.229 ;
     RECT  28.032 5.653 29.712 6.229 ;
     RECT  12.24 5.747 14.856 6.323 ;
     RECT  17.376 5.747 20.76 6.371 ;
     RECT  21.888 6.229 25.224 6.805 ;
     RECT  17.424 6.371 20.76 7.379 ;
     RECT  10.944 5.171 10.968 7.765 ;
     RECT  27.648 6.229 29.712 7.765 ;
     RECT  21.888 6.805 25.368 7.909 ;
     RECT  10.608 7.765 10.968 8.003 ;
     RECT  14.832 6.323 14.856 8.003 ;
     RECT  12.24 6.323 13.512 8.245 ;
     RECT  5.184 6.133 5.208 8.291 ;
     RECT  12.24 8.245 13.656 8.387 ;
     RECT  10.608 8.003 10.632 8.579 ;
     RECT  17.424 7.379 17.448 8.579 ;
     RECT  27.552 7.765 29.712 8.579 ;
     RECT  21.792 7.909 25.368 8.821 ;
     RECT  21.792 8.821 25.704 8.965 ;
     RECT  18.432 7.379 20.76 9.155 ;
     RECT  28.368 8.579 29.712 9.637 ;
     RECT  21.792 8.965 26.856 10.117 ;
     RECT  28.032 9.637 29.712 10.117 ;
     RECT  6.576 5.891 6.6 10.883 ;
     RECT  18.432 9.155 20.088 10.883 ;
     RECT  21.792 10.117 29.712 11.459 ;
     RECT  18.432 10.883 20.04 11.603 ;
     RECT  7.8 6.131 8.76 11.941 ;
     RECT  16.128 5.747 16.152 12.035 ;
     RECT  29.232 11.459 29.712 12.275 ;
     RECT  21.792 11.459 28.104 12.517 ;
     RECT  12.24 8.387 13.512 12.563 ;
     RECT  18.432 11.603 18.912 12.565 ;
     RECT  19.968 11.603 20.04 12.611 ;
     RECT  19.968 12.611 19.992 12.707 ;
     RECT  12.576 12.563 13.512 12.757 ;
     RECT  14.784 9.925 14.808 12.757 ;
     RECT  7.8 11.941 9.624 12.803 ;
     RECT  18.336 12.565 18.912 12.901 ;
     RECT  12.576 12.757 14.808 13.043 ;
     RECT  7.8 12.803 8.76 13.139 ;
     RECT  18.288 12.901 18.912 13.139 ;
     RECT  12.576 13.043 14.424 13.667 ;
     RECT  21.792 12.517 28.392 14.723 ;
     RECT  18.336 13.139 18.912 14.773 ;
     RECT  16.368 14.869 16.392 15.011 ;
     RECT  21.792 14.723 21.816 15.205 ;
     RECT  18.192 14.773 18.912 15.301 ;
     RECT  22.944 14.723 28.392 15.829 ;
     RECT  29.4 12.275 29.712 15.829 ;
     RECT  18.192 15.301 19.464 16.163 ;
     RECT  18.192 16.163 18.912 16.309 ;
     RECT  21.648 15.205 21.816 16.357 ;
     RECT  22.944 15.829 29.712 16.357 ;
     RECT  21.648 16.357 29.712 16.595 ;
     RECT  20.496 16.837 20.52 17.699 ;
     RECT  20.064 18.229 20.088 18.707 ;
     RECT  13.2 13.667 14.424 18.947 ;
     RECT  17.712 16.309 18.912 19.955 ;
     RECT  30.768 19.765 30.792 19.955 ;
     RECT  22.368 16.595 29.712 21.013 ;
     RECT  22.176 21.013 29.712 21.109 ;
     RECT  13.2 18.947 14.232 21.155 ;
     RECT  22.128 21.109 29.712 21.397 ;
     RECT  21.648 21.397 29.712 21.539 ;
     RECT  0.192 19.813 0.216 21.635 ;
     RECT  18.048 19.955 18.912 21.779 ;
     RECT  22.128 21.539 29.712 21.779 ;
     RECT  22.32 21.779 29.712 22.451 ;
     RECT  30.768 24.037 30.792 24.227 ;
     RECT  22.368 22.451 29.712 24.469 ;
     RECT  20.736 23.893 20.76 25.139 ;
     RECT  22.176 24.469 29.712 26.243 ;
     RECT  30.768 28.261 30.792 29.315 ;
     RECT  23.136 26.243 29.712 29.795 ;
     RECT  30.768 30.613 30.792 30.803 ;
     RECT  24 29.795 29.712 33.683 ;
     RECT  25.488 33.683 29.712 33.731 ;
     RECT  25.92 33.731 29.712 34.067 ;
     RECT  26.4 34.067 29.712 34.835 ;
     RECT  26.4 34.835 27.912 35.027 ;
     RECT  26.592 35.027 27.912 35.075 ;
     RECT  26.592 35.075 27.864 35.171 ;
     RECT  26.688 35.171 27.864 35.363 ;
     RECT  27.696 35.363 27.864 35.411 ;
     RECT  27.696 35.411 27.72 35.459 ;
     RECT  2.4 2.151 2.712 41.049 ;
     RECT  7.8 13.139 8.112 41.049 ;
     RECT  13.2 21.155 13.512 41.049 ;
     RECT  18.6 21.779 18.912 41.049 ;
     RECT  24 33.683 24.312 41.049 ;
     RECT  29.4 34.835 29.712 41.049 ;
     RECT  2.4 41.049 2.52 41.063 ;
     RECT  7.8 41.049 7.92 41.063 ;
     RECT  13.2 41.049 13.32 41.063 ;
     RECT  18.6 41.049 18.72 41.063 ;
     RECT  24 41.049 24.12 41.063 ;
     RECT  29.4 41.049 29.52 41.063 ;
     RECT  10.488 1.907 11.616 3.925 ;
     RECT  15 2.387 16.416 3.397 ;
     RECT  24.984 2.915 26.016 4.595 ;
     RECT  15 3.397 16.128 5.747 ;
     RECT  24.984 4.595 26.208 4.643 ;
     RECT  24.984 4.643 26.256 5.555 ;
     RECT  10.968 4.739 12.24 8.003 ;
     RECT  5.952 5.171 6.576 6.133 ;
     RECT  9.96 5.171 10.944 5.219 ;
     RECT  9.672 5.219 10.944 5.891 ;
     RECT  24.984 5.555 25.368 6.229 ;
     RECT  14.856 5.747 16.128 8.003 ;
     RECT  16.152 5.747 17.376 6.371 ;
     RECT  20.76 5.747 21.888 7.909 ;
     RECT  6.6 5.891 7.8 10.883 ;
     RECT  5.208 6.133 6.576 8.291 ;
     RECT  25.224 6.229 25.368 6.805 ;
     RECT  13.512 6.323 14.832 8.003 ;
     RECT  16.152 6.371 17.424 8.579 ;
     RECT  17.448 7.379 18.432 8.579 ;
     RECT  20.76 7.909 21.792 9.155 ;
     RECT  13.512 8.003 13.656 8.245 ;
     RECT  27.552 8.579 28.368 8.965 ;
     RECT  26.856 8.965 28.368 9.637 ;
     RECT  26.856 9.637 28.032 10.117 ;
     RECT  13.512 9.925 14.784 12.757 ;
     RECT  14.808 9.925 16.128 12.035 ;
     RECT  28.104 11.459 29.232 12.275 ;
     RECT  18.912 11.603 19.968 12.707 ;
     RECT  28.104 12.275 29.4 12.517 ;
     RECT  28.392 12.517 29.4 15.829 ;
     RECT  21.816 14.723 22.944 16.357 ;
     RECT  18.912 18.229 20.064 18.707 ;
     RECT  29.712 19.765 30.768 19.955 ;
     RECT  29.712 24.037 30.768 24.227 ;
     RECT  20.76 24.469 22.176 25.139 ;
     RECT  29.712 28.261 30.768 29.315 ;
     RECT  29.712 29.315 30.792 30.613 ;
     RECT  29.712 30.613 30.768 30.803 ;
     RECT  24.312 33.683 25.488 33.731 ;
     RECT  27.912 34.835 29.4 35.075 ;
  END
END ot_qkh_head_stin_native
END LIBRARY
